VERSION 5.7 ;
  NOWIREEXTENSIONATPIN ON ;
  DIVIDERCHAR "/" ;
  BUSBITCHARS "[]" ;
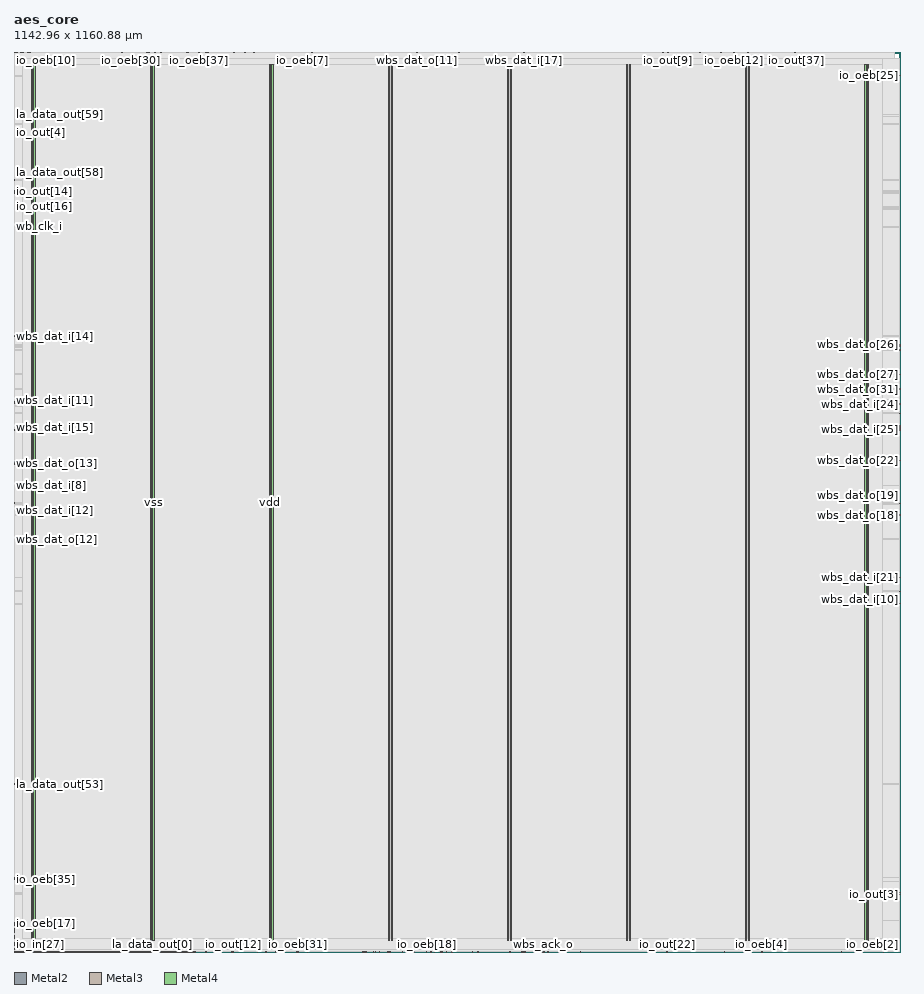
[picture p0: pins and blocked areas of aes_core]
MACRO aes_core
  CLASS BLOCK ;
  FOREIGN aes_core ;
  ORIGIN 0.000 0.000 ;
  SIZE 1142.960 BY 1160.880 ;
  PIN io_in[0]
    DIRECTION INPUT ;
    USE SIGNAL ;
    PORT
      LAYER Metal2 ;
        RECT 4.480 0.000 5.040 0.560 ;
    END
  END io_in[0]
  PIN io_in[10]
    DIRECTION INPUT ;
    USE SIGNAL ;
    PORT
      LAYER Metal2 ;
        RECT 12.320 0.000 12.880 0.560 ;
    END
  END io_in[10]
  PIN io_in[11]
    DIRECTION INPUT ;
    USE SIGNAL ;
    PORT
      LAYER Metal2 ;
        RECT 112.000 0.000 112.560 0.560 ;
    END
  END io_in[11]
  PIN io_in[12]
    DIRECTION INPUT ;
    USE SIGNAL ;
    PORT
      LAYER Metal2 ;
        RECT 13.440 0.000 14.000 0.560 ;
    END
  END io_in[12]
  PIN io_in[13]
    DIRECTION INPUT ;
    USE SIGNAL ;
    PORT
      LAYER Metal2 ;
        RECT 6.720 0.000 7.280 0.560 ;
    END
  END io_in[13]
  PIN io_in[14]
    DIRECTION INPUT ;
    USE SIGNAL ;
    PORT
      LAYER Metal2 ;
        RECT 10.080 0.000 10.640 0.560 ;
    END
  END io_in[14]
  PIN io_in[15]
    DIRECTION INPUT ;
    USE SIGNAL ;
    PORT
      LAYER Metal2 ;
        RECT 8.960 0.000 9.520 0.560 ;
    END
  END io_in[15]
  PIN io_in[16]
    DIRECTION INPUT ;
    USE SIGNAL ;
    PORT
      LAYER Metal2 ;
        RECT 16.800 0.000 17.360 0.560 ;
    END
  END io_in[16]
  PIN io_in[17]
    DIRECTION INPUT ;
    USE SIGNAL ;
    PORT
      LAYER Metal2 ;
        RECT 21.280 0.000 21.840 0.560 ;
    END
  END io_in[17]
  PIN io_in[18]
    DIRECTION INPUT ;
    USE SIGNAL ;
    PORT
      LAYER Metal2 ;
        RECT 14.560 0.000 15.120 0.560 ;
    END
  END io_in[18]
  PIN io_in[19]
    DIRECTION INPUT ;
    USE SIGNAL ;
    PORT
      LAYER Metal2 ;
        RECT 23.520 0.000 24.080 0.560 ;
    END
  END io_in[19]
  PIN io_in[1]
    DIRECTION INPUT ;
    USE SIGNAL ;
    PORT
      LAYER Metal2 ;
        RECT 22.400 0.000 22.960 0.560 ;
    END
  END io_in[1]
  PIN io_in[20]
    DIRECTION INPUT ;
    USE SIGNAL ;
    PORT
      LAYER Metal2 ;
        RECT 15.680 0.000 16.240 0.560 ;
    END
  END io_in[20]
  PIN io_in[21]
    DIRECTION INPUT ;
    USE SIGNAL ;
    PORT
      LAYER Metal2 ;
        RECT 19.040 0.000 19.600 0.560 ;
    END
  END io_in[21]
  PIN io_in[22]
    DIRECTION INPUT ;
    USE SIGNAL ;
    PORT
      LAYER Metal2 ;
        RECT 17.920 0.000 18.480 0.560 ;
    END
  END io_in[22]
  PIN io_in[23]
    DIRECTION INPUT ;
    USE SIGNAL ;
    PORT
      LAYER Metal2 ;
        RECT 25.760 0.000 26.320 0.560 ;
    END
  END io_in[23]
  PIN io_in[24]
    DIRECTION INPUT ;
    USE SIGNAL ;
    PORT
      LAYER Metal2 ;
        RECT 20.160 0.000 20.720 0.560 ;
    END
  END io_in[24]
  PIN io_in[25]
    DIRECTION INPUT ;
    USE SIGNAL ;
    PORT
      LAYER Metal2 ;
        RECT 31.360 0.000 31.920 0.560 ;
    END
  END io_in[25]
  PIN io_in[26]
    DIRECTION INPUT ;
    USE SIGNAL ;
    PORT
      LAYER Metal2 ;
        RECT 30.240 0.000 30.800 0.560 ;
    END
  END io_in[26]
  PIN io_in[27]
    DIRECTION INPUT ;
    USE SIGNAL ;
    PORT
      LAYER Metal2 ;
        RECT 33.600 0.000 34.160 0.560 ;
    END
  END io_in[27]
  PIN io_in[28]
    DIRECTION INPUT ;
    USE SIGNAL ;
    PORT
      LAYER Metal2 ;
        RECT 24.640 0.000 25.200 0.560 ;
    END
  END io_in[28]
  PIN io_in[29]
    DIRECTION INPUT ;
    USE SIGNAL ;
    PORT
      LAYER Metal2 ;
        RECT 28.000 0.000 28.560 0.560 ;
    END
  END io_in[29]
  PIN io_in[2]
    DIRECTION INPUT ;
    USE SIGNAL ;
    PORT
      LAYER Metal2 ;
        RECT 26.880 0.000 27.440 0.560 ;
    END
  END io_in[2]
  PIN io_in[30]
    DIRECTION INPUT ;
    USE SIGNAL ;
    PORT
      LAYER Metal2 ;
        RECT 34.720 0.000 35.280 0.560 ;
    END
  END io_in[30]
  PIN io_in[31]
    DIRECTION INPUT ;
    USE SIGNAL ;
    PORT
      LAYER Metal2 ;
        RECT 29.120 0.000 29.680 0.560 ;
    END
  END io_in[31]
  PIN io_in[32]
    DIRECTION INPUT ;
    USE SIGNAL ;
    PORT
      LAYER Metal2 ;
        RECT 32.480 0.000 33.040 0.560 ;
    END
  END io_in[32]
  PIN io_in[33]
    DIRECTION INPUT ;
    USE SIGNAL ;
    PORT
      LAYER Metal2 ;
        RECT 39.200 0.000 39.760 0.560 ;
    END
  END io_in[33]
  PIN io_in[34]
    DIRECTION INPUT ;
    USE SIGNAL ;
    PORT
      LAYER Metal2 ;
        RECT 40.320 0.000 40.880 0.560 ;
    END
  END io_in[34]
  PIN io_in[35]
    DIRECTION INPUT ;
    USE SIGNAL ;
    PORT
      LAYER Metal2 ;
        RECT 43.680 0.000 44.240 0.560 ;
    END
  END io_in[35]
  PIN io_in[36]
    DIRECTION INPUT ;
    USE SIGNAL ;
    PORT
      LAYER Metal2 ;
        RECT 36.960 0.000 37.520 0.560 ;
    END
  END io_in[36]
  PIN io_in[37]
    DIRECTION INPUT ;
    USE SIGNAL ;
    PORT
      LAYER Metal2 ;
        RECT 35.840 0.000 36.400 0.560 ;
    END
  END io_in[37]
  PIN io_in[3]
    DIRECTION INPUT ;
    USE SIGNAL ;
    PORT
      LAYER Metal2 ;
        RECT 47.040 0.000 47.600 0.560 ;
    END
  END io_in[3]
  PIN io_in[4]
    DIRECTION INPUT ;
    USE SIGNAL ;
    PORT
      LAYER Metal2 ;
        RECT 38.080 0.000 38.640 0.560 ;
    END
  END io_in[4]
  PIN io_in[5]
    DIRECTION INPUT ;
    USE SIGNAL ;
    PORT
      LAYER Metal2 ;
        RECT 41.440 0.000 42.000 0.560 ;
    END
  END io_in[5]
  PIN io_in[6]
    DIRECTION INPUT ;
    USE SIGNAL ;
    PORT
      LAYER Metal2 ;
        RECT 48.160 0.000 48.720 0.560 ;
    END
  END io_in[6]
  PIN io_in[7]
    DIRECTION INPUT ;
    USE SIGNAL ;
    PORT
      LAYER Metal2 ;
        RECT 49.280 0.000 49.840 0.560 ;
    END
  END io_in[7]
  PIN io_in[8]
    DIRECTION INPUT ;
    USE SIGNAL ;
    PORT
      LAYER Metal2 ;
        RECT 42.560 0.000 43.120 0.560 ;
    END
  END io_in[8]
  PIN io_in[9]
    DIRECTION INPUT ;
    USE SIGNAL ;
    PORT
      LAYER Metal2 ;
        RECT 45.920 0.000 46.480 0.560 ;
    END
  END io_in[9]
  PIN io_oeb[0]
    DIRECTION OUTPUT ;
    USE SIGNAL ;
    ANTENNADIFFAREA 0.360800 ;
    PORT
      LAYER Metal2 ;
        RECT 265.440 0.000 266.000 0.560 ;
    END
  END io_oeb[0]
  PIN io_oeb[10]
    DIRECTION OUTPUT ;
    USE SIGNAL ;
    ANTENNADIFFAREA 0.360800 ;
    PORT
      LAYER Metal2 ;
        RECT 15.680 1160.320 16.240 1160.880 ;
    END
  END io_oeb[10]
  PIN io_oeb[11]
    DIRECTION OUTPUT ;
    USE SIGNAL ;
    ANTENNADIFFAREA 0.360800 ;
    PORT
      LAYER Metal3 ;
        RECT 0.000 3.360 0.560 3.920 ;
    END
  END io_oeb[11]
  PIN io_oeb[12]
    DIRECTION OUTPUT ;
    USE SIGNAL ;
    ANTENNADIFFAREA 0.360800 ;
    PORT
      LAYER Metal2 ;
        RECT 928.480 1160.320 929.040 1160.880 ;
    END
  END io_oeb[12]
  PIN io_oeb[13]
    DIRECTION OUTPUT ;
    USE SIGNAL ;
    ANTENNADIFFAREA 0.360800 ;
    PORT
      LAYER Metal3 ;
        RECT 0.000 10.080 0.560 10.640 ;
    END
  END io_oeb[13]
  PIN io_oeb[14]
    DIRECTION OUTPUT ;
    USE SIGNAL ;
    ANTENNADIFFAREA 0.360800 ;
    PORT
      LAYER Metal2 ;
        RECT 916.160 0.000 916.720 0.560 ;
    END
  END io_oeb[14]
  PIN io_oeb[15]
    DIRECTION OUTPUT ;
    USE SIGNAL ;
    ANTENNADIFFAREA 0.360800 ;
    PORT
      LAYER Metal3 ;
        RECT 0.000 31.360 0.560 31.920 ;
    END
  END io_oeb[15]
  PIN io_oeb[16]
    DIRECTION OUTPUT ;
    USE SIGNAL ;
    ANTENNADIFFAREA 0.360800 ;
    PORT
      LAYER Metal2 ;
        RECT 2.240 1160.320 2.800 1160.880 ;
    END
  END io_oeb[16]
  PIN io_oeb[17]
    DIRECTION OUTPUT ;
    USE SIGNAL ;
    ANTENNADIFFAREA 0.360800 ;
    PORT
      LAYER Metal3 ;
        RECT 0.000 35.840 0.560 36.400 ;
    END
  END io_oeb[17]
  PIN io_oeb[18]
    DIRECTION OUTPUT ;
    USE SIGNAL ;
    ANTENNADIFFAREA 0.360800 ;
    PORT
      LAYER Metal2 ;
        RECT 532.000 0.000 532.560 0.560 ;
    END
  END io_oeb[18]
  PIN io_oeb[19]
    DIRECTION OUTPUT ;
    USE SIGNAL ;
    ANTENNADIFFAREA 0.360800 ;
    PORT
      LAYER Metal2 ;
        RECT 7.840 1160.320 8.400 1160.880 ;
    END
  END io_oeb[19]
  PIN io_oeb[1]
    DIRECTION OUTPUT ;
    USE SIGNAL ;
    ANTENNADIFFAREA 0.360800 ;
    PORT
      LAYER Metal2 ;
        RECT 182.560 1160.320 183.120 1160.880 ;
    END
  END io_oeb[1]
  PIN io_oeb[20]
    DIRECTION OUTPUT ;
    USE SIGNAL ;
    ANTENNADIFFAREA 0.360800 ;
    PORT
      LAYER Metal2 ;
        RECT 172.480 1160.320 173.040 1160.880 ;
    END
  END io_oeb[20]
  PIN io_oeb[21]
    DIRECTION OUTPUT ;
    USE SIGNAL ;
    ANTENNADIFFAREA 0.360800 ;
    PORT
      LAYER Metal3 ;
        RECT 0.000 29.120 0.560 29.680 ;
    END
  END io_oeb[21]
  PIN io_oeb[22]
    DIRECTION OUTPUT ;
    USE SIGNAL ;
    ANTENNADIFFAREA 0.360800 ;
    PORT
      LAYER Metal2 ;
        RECT 16.800 1160.320 17.360 1160.880 ;
    END
  END io_oeb[22]
  PIN io_oeb[23]
    DIRECTION OUTPUT ;
    USE SIGNAL ;
    ANTENNADIFFAREA 0.360800 ;
    PORT
      LAYER Metal2 ;
        RECT 1.120 1160.320 1.680 1160.880 ;
    END
  END io_oeb[23]
  PIN io_oeb[24]
    DIRECTION OUTPUT ;
    USE SIGNAL ;
    ANTENNADIFFAREA 0.360800 ;
    PORT
      LAYER Metal3 ;
        RECT 0.000 19.040 0.560 19.600 ;
    END
  END io_oeb[24]
  PIN io_oeb[25]
    DIRECTION OUTPUT ;
    USE SIGNAL ;
    ANTENNADIFFAREA 0.360800 ;
    PORT
      LAYER Metal3 ;
        RECT 1142.400 1130.080 1142.960 1130.640 ;
    END
  END io_oeb[25]
  PIN io_oeb[26]
    DIRECTION OUTPUT ;
    USE SIGNAL ;
    ANTENNADIFFAREA 0.360800 ;
    PORT
      LAYER Metal3 ;
        RECT 0.000 32.480 0.560 33.040 ;
    END
  END io_oeb[26]
  PIN io_oeb[27]
    DIRECTION OUTPUT ;
    USE SIGNAL ;
    ANTENNADIFFAREA 0.360800 ;
    PORT
      LAYER Metal3 ;
        RECT 0.000 8.960 0.560 9.520 ;
    END
  END io_oeb[27]
  PIN io_oeb[28]
    DIRECTION OUTPUT ;
    USE SIGNAL ;
    ANTENNADIFFAREA 0.360800 ;
    PORT
      LAYER Metal3 ;
        RECT 0.000 17.920 0.560 18.480 ;
    END
  END io_oeb[28]
  PIN io_oeb[29]
    DIRECTION OUTPUT ;
    USE SIGNAL ;
    ANTENNADIFFAREA 0.360800 ;
    PORT
      LAYER Metal2 ;
        RECT 549.920 0.000 550.480 0.560 ;
    END
  END io_oeb[29]
  PIN io_oeb[2]
    DIRECTION OUTPUT ;
    USE SIGNAL ;
    ANTENNADIFFAREA 0.360800 ;
    PORT
      LAYER Metal2 ;
        RECT 1121.120 0.000 1121.680 0.560 ;
    END
  END io_oeb[2]
  PIN io_oeb[30]
    DIRECTION OUTPUT ;
    USE SIGNAL ;
    ANTENNADIFFAREA 0.360800 ;
    PORT
      LAYER Metal2 ;
        RECT 150.080 1160.320 150.640 1160.880 ;
    END
  END io_oeb[30]
  PIN io_oeb[31]
    DIRECTION OUTPUT ;
    USE SIGNAL ;
    ANTENNADIFFAREA 0.360800 ;
    PORT
      LAYER Metal2 ;
        RECT 366.240 0.000 366.800 0.560 ;
    END
  END io_oeb[31]
  PIN io_oeb[32]
    DIRECTION OUTPUT ;
    USE SIGNAL ;
    ANTENNADIFFAREA 0.360800 ;
    PORT
      LAYER Metal2 ;
        RECT 21.280 1160.320 21.840 1160.880 ;
    END
  END io_oeb[32]
  PIN io_oeb[33]
    DIRECTION OUTPUT ;
    USE SIGNAL ;
    ANTENNADIFFAREA 0.360800 ;
    PORT
      LAYER Metal2 ;
        RECT 171.360 1160.320 171.920 1160.880 ;
    END
  END io_oeb[33]
  PIN io_oeb[34]
    DIRECTION OUTPUT ;
    USE SIGNAL ;
    ANTENNADIFFAREA 0.360800 ;
    PORT
      LAYER Metal2 ;
        RECT 173.600 1160.320 174.160 1160.880 ;
    END
  END io_oeb[34]
  PIN io_oeb[35]
    DIRECTION OUTPUT ;
    USE SIGNAL ;
    ANTENNADIFFAREA 0.360800 ;
    PORT
      LAYER Metal3 ;
        RECT 0.000 92.960 0.560 93.520 ;
    END
  END io_oeb[35]
  PIN io_oeb[36]
    DIRECTION OUTPUT ;
    USE SIGNAL ;
    ANTENNADIFFAREA 0.360800 ;
    PORT
      LAYER Metal2 ;
        RECT 946.400 1160.320 946.960 1160.880 ;
    END
  END io_oeb[36]
  PIN io_oeb[37]
    DIRECTION OUTPUT ;
    USE SIGNAL ;
    ANTENNADIFFAREA 0.360800 ;
    PORT
      LAYER Metal2 ;
        RECT 238.560 1160.320 239.120 1160.880 ;
    END
  END io_oeb[37]
  PIN io_oeb[3]
    DIRECTION OUTPUT ;
    USE SIGNAL ;
    ANTENNADIFFAREA 0.360800 ;
    PORT
      LAYER Metal2 ;
        RECT 14.560 1160.320 15.120 1160.880 ;
    END
  END io_oeb[3]
  PIN io_oeb[4]
    DIRECTION OUTPUT ;
    USE SIGNAL ;
    ANTENNADIFFAREA 0.360800 ;
    PORT
      LAYER Metal2 ;
        RECT 964.320 0.000 964.880 0.560 ;
    END
  END io_oeb[4]
  PIN io_oeb[5]
    DIRECTION OUTPUT ;
    USE SIGNAL ;
    ANTENNADIFFAREA 0.360800 ;
    PORT
      LAYER Metal3 ;
        RECT 0.000 20.160 0.560 20.720 ;
    END
  END io_oeb[5]
  PIN io_oeb[6]
    DIRECTION OUTPUT ;
    USE SIGNAL ;
    ANTENNADIFFAREA 0.360800 ;
    PORT
      LAYER Metal2 ;
        RECT 247.520 0.000 248.080 0.560 ;
    END
  END io_oeb[6]
  PIN io_oeb[7]
    DIRECTION OUTPUT ;
    USE SIGNAL ;
    ANTENNADIFFAREA 0.360800 ;
    PORT
      LAYER Metal2 ;
        RECT 371.840 1160.320 372.400 1160.880 ;
    END
  END io_oeb[7]
  PIN io_oeb[8]
    DIRECTION OUTPUT ;
    USE SIGNAL ;
    ANTENNADIFFAREA 0.360800 ;
    PORT
      LAYER Metal2 ;
        RECT 11.200 1160.320 11.760 1160.880 ;
    END
  END io_oeb[8]
  PIN io_oeb[9]
    DIRECTION OUTPUT ;
    USE SIGNAL ;
    ANTENNADIFFAREA 0.360800 ;
    PORT
      LAYER Metal3 ;
        RECT 0.000 28.000 0.560 28.560 ;
    END
  END io_oeb[9]
  PIN io_out[0]
    DIRECTION OUTPUT ;
    USE SIGNAL ;
    ANTENNADIFFAREA 0.360800 ;
    PORT
      LAYER Metal2 ;
        RECT 176.960 1160.320 177.520 1160.880 ;
    END
  END io_out[0]
  PIN io_out[10]
    DIRECTION OUTPUT ;
    USE SIGNAL ;
    ANTENNADIFFAREA 0.360800 ;
    PORT
      LAYER Metal2 ;
        RECT 178.080 1160.320 178.640 1160.880 ;
    END
  END io_out[10]
  PIN io_out[11]
    DIRECTION OUTPUT ;
    USE SIGNAL ;
    ANTENNADIFFAREA 0.360800 ;
    PORT
      LAYER Metal2 ;
        RECT 123.200 0.000 123.760 0.560 ;
    END
  END io_out[11]
  PIN io_out[12]
    DIRECTION OUTPUT ;
    USE SIGNAL ;
    ANTENNADIFFAREA 0.360800 ;
    PORT
      LAYER Metal2 ;
        RECT 282.240 0.000 282.800 0.560 ;
    END
  END io_out[12]
  PIN io_out[13]
    DIRECTION OUTPUT ;
    USE SIGNAL ;
    ANTENNADIFFAREA 0.360800 ;
    PORT
      LAYER Metal2 ;
        RECT 10.080 1160.320 10.640 1160.880 ;
    END
  END io_out[13]
  PIN io_out[14]
    DIRECTION OUTPUT ;
    USE SIGNAL ;
    ANTENNADIFFAREA 0.360800 ;
    PORT
      LAYER Metal3 ;
        RECT 0.000 981.120 0.560 981.680 ;
    END
  END io_out[14]
  PIN io_out[15]
    DIRECTION OUTPUT ;
    USE SIGNAL ;
    ANTENNADIFFAREA 0.360800 ;
    PORT
      LAYER Metal3 ;
        RECT 0.000 95.200 0.560 95.760 ;
    END
  END io_out[15]
  PIN io_out[16]
    DIRECTION OUTPUT ;
    USE SIGNAL ;
    ANTENNADIFFAREA 0.360800 ;
    PORT
      LAYER Metal3 ;
        RECT 0.000 960.960 0.560 961.520 ;
    END
  END io_out[16]
  PIN io_out[17]
    DIRECTION OUTPUT ;
    USE SIGNAL ;
    ANTENNADIFFAREA 0.360800 ;
    PORT
      LAYER Metal2 ;
        RECT 364.000 0.000 364.560 0.560 ;
    END
  END io_out[17]
  PIN io_out[18]
    DIRECTION OUTPUT ;
    USE SIGNAL ;
    ANTENNADIFFAREA 0.360800 ;
    PORT
      LAYER Metal3 ;
        RECT 0.000 7.840 0.560 8.400 ;
    END
  END io_out[18]
  PIN io_out[19]
    DIRECTION OUTPUT ;
    USE SIGNAL ;
    ANTENNADIFFAREA 0.360800 ;
    PORT
      LAYER Metal2 ;
        RECT 20.160 1160.320 20.720 1160.880 ;
    END
  END io_out[19]
  PIN io_out[1]
    DIRECTION OUTPUT ;
    USE SIGNAL ;
    ANTENNADIFFAREA 0.360800 ;
    PORT
      LAYER Metal3 ;
        RECT 0.000 38.080 0.560 38.640 ;
    END
  END io_out[1]
  PIN io_out[20]
    DIRECTION OUTPUT ;
    USE SIGNAL ;
    ANTENNADIFFAREA 0.360800 ;
    PORT
      LAYER Metal2 ;
        RECT 284.480 1160.320 285.040 1160.880 ;
    END
  END io_out[20]
  PIN io_out[21]
    DIRECTION OUTPUT ;
    USE SIGNAL ;
    ANTENNADIFFAREA 0.360800 ;
    PORT
      LAYER Metal2 ;
        RECT 884.800 1160.320 885.360 1160.880 ;
    END
  END io_out[21]
  PIN io_out[22]
    DIRECTION OUTPUT ;
    USE SIGNAL ;
    ANTENNADIFFAREA 0.360800 ;
    PORT
      LAYER Metal2 ;
        RECT 842.240 0.000 842.800 0.560 ;
    END
  END io_out[22]
  PIN io_out[23]
    DIRECTION OUTPUT ;
    USE SIGNAL ;
    ANTENNADIFFAREA 0.360800 ;
    PORT
      LAYER Metal2 ;
        RECT 3.360 1160.320 3.920 1160.880 ;
    END
  END io_out[23]
  PIN io_out[24]
    DIRECTION OUTPUT ;
    USE SIGNAL ;
    ANTENNADIFFAREA 0.360800 ;
    PORT
      LAYER Metal3 ;
        RECT 0.000 978.880 0.560 979.440 ;
    END
  END io_out[24]
  PIN io_out[25]
    DIRECTION OUTPUT ;
    USE SIGNAL ;
    ANTENNADIFFAREA 0.360800 ;
    PORT
      LAYER Metal2 ;
        RECT 104.160 0.000 104.720 0.560 ;
    END
  END io_out[25]
  PIN io_out[26]
    DIRECTION OUTPUT ;
    USE SIGNAL ;
    ANTENNADIFFAREA 0.360800 ;
    PORT
      LAYER Metal2 ;
        RECT 138.880 0.000 139.440 0.560 ;
    END
  END io_out[26]
  PIN io_out[27]
    DIRECTION OUTPUT ;
    USE SIGNAL ;
    ANTENNADIFFAREA 0.360800 ;
    PORT
      LAYER Metal2 ;
        RECT 324.800 0.000 325.360 0.560 ;
    END
  END io_out[27]
  PIN io_out[28]
    DIRECTION OUTPUT ;
    USE SIGNAL ;
    ANTENNADIFFAREA 0.360800 ;
    PORT
      LAYER Metal2 ;
        RECT 175.840 1160.320 176.400 1160.880 ;
    END
  END io_out[28]
  PIN io_out[29]
    DIRECTION OUTPUT ;
    USE SIGNAL ;
    ANTENNADIFFAREA 0.360800 ;
    PORT
      LAYER Metal2 ;
        RECT 841.120 0.000 841.680 0.560 ;
    END
  END io_out[29]
  PIN io_out[2]
    DIRECTION OUTPUT ;
    USE SIGNAL ;
    ANTENNADIFFAREA 0.360800 ;
    PORT
      LAYER Metal2 ;
        RECT 17.920 1160.320 18.480 1160.880 ;
    END
  END io_out[2]
  PIN io_out[30]
    DIRECTION OUTPUT ;
    USE SIGNAL ;
    ANTENNADIFFAREA 0.360800 ;
    PORT
      LAYER Metal2 ;
        RECT 13.440 1160.320 14.000 1160.880 ;
    END
  END io_out[30]
  PIN io_out[31]
    DIRECTION OUTPUT ;
    USE SIGNAL ;
    ANTENNADIFFAREA 0.360800 ;
    PORT
      LAYER Metal2 ;
        RECT 216.160 0.000 216.720 0.560 ;
    END
  END io_out[31]
  PIN io_out[32]
    DIRECTION OUTPUT ;
    USE SIGNAL ;
    ANTENNADIFFAREA 0.360800 ;
    PORT
      LAYER Metal2 ;
        RECT 313.600 0.000 314.160 0.560 ;
    END
  END io_out[32]
  PIN io_out[33]
    DIRECTION OUTPUT ;
    USE SIGNAL ;
    ANTENNADIFFAREA 0.360800 ;
    PORT
      LAYER Metal2 ;
        RECT 247.520 1160.320 248.080 1160.880 ;
    END
  END io_out[33]
  PIN io_out[34]
    DIRECTION OUTPUT ;
    USE SIGNAL ;
    ANTENNADIFFAREA 0.360800 ;
    PORT
      LAYER Metal2 ;
        RECT 384.160 1160.320 384.720 1160.880 ;
    END
  END io_out[34]
  PIN io_out[35]
    DIRECTION OUTPUT ;
    USE SIGNAL ;
    ANTENNADIFFAREA 0.360800 ;
    PORT
      LAYER Metal2 ;
        RECT 280.000 0.000 280.560 0.560 ;
    END
  END io_out[35]
  PIN io_out[36]
    DIRECTION OUTPUT ;
    USE SIGNAL ;
    ANTENNADIFFAREA 0.360800 ;
    PORT
      LAYER Metal2 ;
        RECT 1067.360 0.000 1067.920 0.560 ;
    END
  END io_out[36]
  PIN io_out[37]
    DIRECTION OUTPUT ;
    USE SIGNAL ;
    ANTENNADIFFAREA 0.360800 ;
    PORT
      LAYER Metal2 ;
        RECT 1009.120 1160.320 1009.680 1160.880 ;
    END
  END io_out[37]
  PIN io_out[3]
    DIRECTION OUTPUT ;
    USE SIGNAL ;
    ANTENNADIFFAREA 0.360800 ;
    PORT
      LAYER Metal3 ;
        RECT 1142.400 73.920 1142.960 74.480 ;
    END
  END io_out[3]
  PIN io_out[4]
    DIRECTION OUTPUT ;
    USE SIGNAL ;
    ANTENNADIFFAREA 0.360800 ;
    PORT
      LAYER Metal3 ;
        RECT 0.000 1067.360 0.560 1067.920 ;
    END
  END io_out[4]
  PIN io_out[5]
    DIRECTION OUTPUT ;
    USE SIGNAL ;
    ANTENNADIFFAREA 0.360800 ;
    PORT
      LAYER Metal3 ;
        RECT 0.000 22.400 0.560 22.960 ;
    END
  END io_out[5]
  PIN io_out[6]
    DIRECTION OUTPUT ;
    USE SIGNAL ;
    ANTENNADIFFAREA 0.360800 ;
    PORT
      LAYER Metal3 ;
        RECT 0.000 24.640 0.560 25.200 ;
    END
  END io_out[6]
  PIN io_out[7]
    DIRECTION OUTPUT ;
    USE SIGNAL ;
    ANTENNADIFFAREA 0.360800 ;
    PORT
      LAYER Metal2 ;
        RECT 236.320 1160.320 236.880 1160.880 ;
    END
  END io_out[7]
  PIN io_out[8]
    DIRECTION OUTPUT ;
    USE SIGNAL ;
    ANTENNADIFFAREA 0.360800 ;
    PORT
      LAYER Metal2 ;
        RECT 91.840 0.000 92.400 0.560 ;
    END
  END io_out[8]
  PIN io_out[9]
    DIRECTION OUTPUT ;
    USE SIGNAL ;
    ANTENNADIFFAREA 0.360800 ;
    PORT
      LAYER Metal2 ;
        RECT 843.360 1160.320 843.920 1160.880 ;
    END
  END io_out[9]
  PIN la_data_in[0]
    DIRECTION INPUT ;
    USE SIGNAL ;
    PORT
      LAYER Metal2 ;
        RECT 44.800 0.000 45.360 0.560 ;
    END
  END la_data_in[0]
  PIN la_data_in[10]
    DIRECTION INPUT ;
    USE SIGNAL ;
    PORT
      LAYER Metal2 ;
        RECT 52.640 0.000 53.200 0.560 ;
    END
  END la_data_in[10]
  PIN la_data_in[11]
    DIRECTION INPUT ;
    USE SIGNAL ;
    PORT
      LAYER Metal2 ;
        RECT 57.120 0.000 57.680 0.560 ;
    END
  END la_data_in[11]
  PIN la_data_in[12]
    DIRECTION INPUT ;
    USE SIGNAL ;
    PORT
      LAYER Metal2 ;
        RECT 50.400 0.000 50.960 0.560 ;
    END
  END la_data_in[12]
  PIN la_data_in[13]
    DIRECTION INPUT ;
    USE SIGNAL ;
    PORT
      LAYER Metal2 ;
        RECT 59.360 0.000 59.920 0.560 ;
    END
  END la_data_in[13]
  PIN la_data_in[14]
    DIRECTION INPUT ;
    USE SIGNAL ;
    PORT
      LAYER Metal2 ;
        RECT 58.240 0.000 58.800 0.560 ;
    END
  END la_data_in[14]
  PIN la_data_in[15]
    DIRECTION INPUT ;
    USE SIGNAL ;
    PORT
      LAYER Metal2 ;
        RECT 51.520 0.000 52.080 0.560 ;
    END
  END la_data_in[15]
  PIN la_data_in[16]
    DIRECTION INPUT ;
    USE SIGNAL ;
    PORT
      LAYER Metal2 ;
        RECT 54.880 0.000 55.440 0.560 ;
    END
  END la_data_in[16]
  PIN la_data_in[17]
    DIRECTION INPUT ;
    USE SIGNAL ;
    PORT
      LAYER Metal2 ;
        RECT 53.760 0.000 54.320 0.560 ;
    END
  END la_data_in[17]
  PIN la_data_in[18]
    DIRECTION INPUT ;
    USE SIGNAL ;
    PORT
      LAYER Metal2 ;
        RECT 61.600 0.000 62.160 0.560 ;
    END
  END la_data_in[18]
  PIN la_data_in[19]
    DIRECTION INPUT ;
    USE SIGNAL ;
    PORT
      LAYER Metal2 ;
        RECT 56.000 0.000 56.560 0.560 ;
    END
  END la_data_in[19]
  PIN la_data_in[1]
    DIRECTION INPUT ;
    USE SIGNAL ;
    PORT
      LAYER Metal2 ;
        RECT 67.200 0.000 67.760 0.560 ;
    END
  END la_data_in[1]
  PIN la_data_in[20]
    DIRECTION INPUT ;
    USE SIGNAL ;
    PORT
      LAYER Metal2 ;
        RECT 66.080 0.000 66.640 0.560 ;
    END
  END la_data_in[20]
  PIN la_data_in[21]
    DIRECTION INPUT ;
    USE SIGNAL ;
    PORT
      LAYER Metal2 ;
        RECT 69.440 0.000 70.000 0.560 ;
    END
  END la_data_in[21]
  PIN la_data_in[22]
    DIRECTION INPUT ;
    USE SIGNAL ;
    PORT
      LAYER Metal2 ;
        RECT 60.480 0.000 61.040 0.560 ;
    END
  END la_data_in[22]
  PIN la_data_in[23]
    DIRECTION INPUT ;
    USE SIGNAL ;
    PORT
      LAYER Metal2 ;
        RECT 63.840 0.000 64.400 0.560 ;
    END
  END la_data_in[23]
  PIN la_data_in[24]
    DIRECTION INPUT ;
    USE SIGNAL ;
    PORT
      LAYER Metal2 ;
        RECT 62.720 0.000 63.280 0.560 ;
    END
  END la_data_in[24]
  PIN la_data_in[25]
    DIRECTION INPUT ;
    USE SIGNAL ;
    PORT
      LAYER Metal2 ;
        RECT 70.560 0.000 71.120 0.560 ;
    END
  END la_data_in[25]
  PIN la_data_in[26]
    DIRECTION INPUT ;
    USE SIGNAL ;
    PORT
      LAYER Metal2 ;
        RECT 64.960 0.000 65.520 0.560 ;
    END
  END la_data_in[26]
  PIN la_data_in[27]
    DIRECTION INPUT ;
    USE SIGNAL ;
    PORT
      LAYER Metal2 ;
        RECT 68.320 0.000 68.880 0.560 ;
    END
  END la_data_in[27]
  PIN la_data_in[28]
    DIRECTION INPUT ;
    USE SIGNAL ;
    PORT
      LAYER Metal2 ;
        RECT 75.040 0.000 75.600 0.560 ;
    END
  END la_data_in[28]
  PIN la_data_in[29]
    DIRECTION INPUT ;
    USE SIGNAL ;
    PORT
      LAYER Metal2 ;
        RECT 76.160 0.000 76.720 0.560 ;
    END
  END la_data_in[29]
  PIN la_data_in[2]
    DIRECTION INPUT ;
    USE SIGNAL ;
    PORT
      LAYER Metal2 ;
        RECT 79.520 0.000 80.080 0.560 ;
    END
  END la_data_in[2]
  PIN la_data_in[30]
    DIRECTION INPUT ;
    USE SIGNAL ;
    PORT
      LAYER Metal2 ;
        RECT 72.800 0.000 73.360 0.560 ;
    END
  END la_data_in[30]
  PIN la_data_in[31]
    DIRECTION INPUT ;
    USE SIGNAL ;
    PORT
      LAYER Metal2 ;
        RECT 71.680 0.000 72.240 0.560 ;
    END
  END la_data_in[31]
  PIN la_data_in[32]
    DIRECTION INPUT ;
    USE SIGNAL ;
    PORT
      LAYER Metal2 ;
        RECT 82.880 0.000 83.440 0.560 ;
    END
  END la_data_in[32]
  PIN la_data_in[33]
    DIRECTION INPUT ;
    USE SIGNAL ;
    PORT
      LAYER Metal2 ;
        RECT 73.920 0.000 74.480 0.560 ;
    END
  END la_data_in[33]
  PIN la_data_in[34]
    DIRECTION INPUT ;
    USE SIGNAL ;
    PORT
      LAYER Metal2 ;
        RECT 77.280 0.000 77.840 0.560 ;
    END
  END la_data_in[34]
  PIN la_data_in[35]
    DIRECTION INPUT ;
    USE SIGNAL ;
    PORT
      LAYER Metal2 ;
        RECT 84.000 0.000 84.560 0.560 ;
    END
  END la_data_in[35]
  PIN la_data_in[36]
    DIRECTION INPUT ;
    USE SIGNAL ;
    PORT
      LAYER Metal2 ;
        RECT 85.120 0.000 85.680 0.560 ;
    END
  END la_data_in[36]
  PIN la_data_in[37]
    DIRECTION INPUT ;
    USE SIGNAL ;
    PORT
      LAYER Metal2 ;
        RECT 78.400 0.000 78.960 0.560 ;
    END
  END la_data_in[37]
  PIN la_data_in[38]
    DIRECTION INPUT ;
    USE SIGNAL ;
    PORT
      LAYER Metal2 ;
        RECT 81.760 0.000 82.320 0.560 ;
    END
  END la_data_in[38]
  PIN la_data_in[39]
    DIRECTION INPUT ;
    USE SIGNAL ;
    PORT
      LAYER Metal2 ;
        RECT 80.640 0.000 81.200 0.560 ;
    END
  END la_data_in[39]
  PIN la_data_in[3]
    DIRECTION INPUT ;
    USE SIGNAL ;
    PORT
      LAYER Metal2 ;
        RECT 88.480 0.000 89.040 0.560 ;
    END
  END la_data_in[3]
  PIN la_data_in[40]
    DIRECTION INPUT ;
    USE SIGNAL ;
    PORT
      LAYER Metal2 ;
        RECT 224.000 0.000 224.560 0.560 ;
    END
  END la_data_in[40]
  PIN la_data_in[41]
    DIRECTION INPUT ;
    USE SIGNAL ;
    PORT
      LAYER Metal2 ;
        RECT 86.240 0.000 86.800 0.560 ;
    END
  END la_data_in[41]
  PIN la_data_in[42]
    DIRECTION INPUT ;
    USE SIGNAL ;
    PORT
      LAYER Metal2 ;
        RECT 92.960 0.000 93.520 0.560 ;
    END
  END la_data_in[42]
  PIN la_data_in[43]
    DIRECTION INPUT ;
    USE SIGNAL ;
    PORT
      LAYER Metal2 ;
        RECT 94.080 0.000 94.640 0.560 ;
    END
  END la_data_in[43]
  PIN la_data_in[44]
    DIRECTION INPUT ;
    USE SIGNAL ;
    PORT
      LAYER Metal2 ;
        RECT 87.360 0.000 87.920 0.560 ;
    END
  END la_data_in[44]
  PIN la_data_in[45]
    DIRECTION INPUT ;
    USE SIGNAL ;
    PORT
      LAYER Metal2 ;
        RECT 218.400 0.000 218.960 0.560 ;
    END
  END la_data_in[45]
  PIN la_data_in[46]
    DIRECTION INPUT ;
    USE SIGNAL ;
    PORT
      LAYER Metal2 ;
        RECT 90.720 0.000 91.280 0.560 ;
    END
  END la_data_in[46]
  PIN la_data_in[47]
    DIRECTION INPUT ;
    USE SIGNAL ;
    PORT
      LAYER Metal2 ;
        RECT 97.440 0.000 98.000 0.560 ;
    END
  END la_data_in[47]
  PIN la_data_in[48]
    DIRECTION INPUT ;
    USE SIGNAL ;
    PORT
      LAYER Metal2 ;
        RECT 96.320 0.000 96.880 0.560 ;
    END
  END la_data_in[48]
  PIN la_data_in[49]
    DIRECTION INPUT ;
    USE SIGNAL ;
    PORT
      LAYER Metal2 ;
        RECT 5.600 0.000 6.160 0.560 ;
    END
  END la_data_in[49]
  PIN la_data_in[4]
    DIRECTION INPUT ;
    USE SIGNAL ;
    PORT
      LAYER Metal2 ;
        RECT 95.200 0.000 95.760 0.560 ;
    END
  END la_data_in[4]
  PIN la_data_in[50]
    DIRECTION INPUT ;
    USE SIGNAL ;
    PORT
      LAYER Metal2 ;
        RECT 100.800 0.000 101.360 0.560 ;
    END
  END la_data_in[50]
  PIN la_data_in[51]
    DIRECTION INPUT ;
    USE SIGNAL ;
    PORT
      LAYER Metal2 ;
        RECT 103.040 0.000 103.600 0.560 ;
    END
  END la_data_in[51]
  PIN la_data_in[52]
    DIRECTION INPUT ;
    USE SIGNAL ;
    PORT
      LAYER Metal2 ;
        RECT 101.920 0.000 102.480 0.560 ;
    END
  END la_data_in[52]
  PIN la_data_in[53]
    DIRECTION INPUT ;
    USE SIGNAL ;
    PORT
      LAYER Metal2 ;
        RECT 99.680 0.000 100.240 0.560 ;
    END
  END la_data_in[53]
  PIN la_data_in[54]
    DIRECTION INPUT ;
    USE SIGNAL ;
    PORT
      LAYER Metal2 ;
        RECT 98.560 0.000 99.120 0.560 ;
    END
  END la_data_in[54]
  PIN la_data_in[55]
    DIRECTION INPUT ;
    USE SIGNAL ;
    PORT
      LAYER Metal2 ;
        RECT 105.280 0.000 105.840 0.560 ;
    END
  END la_data_in[55]
  PIN la_data_in[56]
    DIRECTION INPUT ;
    USE SIGNAL ;
    PORT
      LAYER Metal2 ;
        RECT 106.400 0.000 106.960 0.560 ;
    END
  END la_data_in[56]
  PIN la_data_in[57]
    DIRECTION INPUT ;
    USE SIGNAL ;
    PORT
      LAYER Metal2 ;
        RECT 7.840 0.000 8.400 0.560 ;
    END
  END la_data_in[57]
  PIN la_data_in[58]
    DIRECTION INPUT ;
    USE SIGNAL ;
    PORT
      LAYER Metal2 ;
        RECT 110.880 0.000 111.440 0.560 ;
    END
  END la_data_in[58]
  PIN la_data_in[59]
    DIRECTION INPUT ;
    USE SIGNAL ;
    PORT
      LAYER Metal2 ;
        RECT 108.640 0.000 109.200 0.560 ;
    END
  END la_data_in[59]
  PIN la_data_in[5]
    DIRECTION INPUT ;
    USE SIGNAL ;
    PORT
      LAYER Metal2 ;
        RECT 221.760 0.000 222.320 0.560 ;
    END
  END la_data_in[5]
  PIN la_data_in[60]
    DIRECTION INPUT ;
    USE SIGNAL ;
    PORT
      LAYER Metal2 ;
        RECT 222.880 0.000 223.440 0.560 ;
    END
  END la_data_in[60]
  PIN la_data_in[61]
    DIRECTION INPUT ;
    USE SIGNAL ;
    PORT
      LAYER Metal2 ;
        RECT 107.520 0.000 108.080 0.560 ;
    END
  END la_data_in[61]
  PIN la_data_in[62]
    DIRECTION INPUT ;
    USE SIGNAL ;
    PORT
      LAYER Metal2 ;
        RECT 116.480 0.000 117.040 0.560 ;
    END
  END la_data_in[62]
  PIN la_data_in[63]
    DIRECTION INPUT ;
    USE SIGNAL ;
    PORT
      LAYER Metal2 ;
        RECT 109.760 0.000 110.320 0.560 ;
    END
  END la_data_in[63]
  PIN la_data_in[6]
    DIRECTION INPUT ;
    USE SIGNAL ;
    PORT
      LAYER Metal2 ;
        RECT 113.120 0.000 113.680 0.560 ;
    END
  END la_data_in[6]
  PIN la_data_in[7]
    DIRECTION INPUT ;
    USE SIGNAL ;
    PORT
      LAYER Metal2 ;
        RECT 220.640 0.000 221.200 0.560 ;
    END
  END la_data_in[7]
  PIN la_data_in[8]
    DIRECTION INPUT ;
    USE SIGNAL ;
    PORT
      LAYER Metal2 ;
        RECT 115.360 0.000 115.920 0.560 ;
    END
  END la_data_in[8]
  PIN la_data_in[9]
    DIRECTION INPUT ;
    USE SIGNAL ;
    PORT
      LAYER Metal2 ;
        RECT 114.240 0.000 114.800 0.560 ;
    END
  END la_data_in[9]
  PIN la_data_out[0]
    DIRECTION OUTPUT ;
    USE SIGNAL ;
    ANTENNADIFFAREA 0.360800 ;
    PORT
      LAYER Metal2 ;
        RECT 178.080 0.000 178.640 0.560 ;
    END
  END la_data_out[0]
  PIN la_data_out[10]
    DIRECTION OUTPUT ;
    USE SIGNAL ;
    ANTENNADIFFAREA 0.360800 ;
    PORT
      LAYER Metal2 ;
        RECT 222.880 1160.320 223.440 1160.880 ;
    END
  END la_data_out[10]
  PIN la_data_out[11]
    DIRECTION OUTPUT ;
    USE SIGNAL ;
    ANTENNADIFFAREA 0.360800 ;
    PORT
      LAYER Metal3 ;
        RECT 0.000 15.680 0.560 16.240 ;
    END
  END la_data_out[11]
  PIN la_data_out[12]
    DIRECTION OUTPUT ;
    USE SIGNAL ;
    ANTENNADIFFAREA 0.360800 ;
    PORT
      LAYER Metal2 ;
        RECT 89.600 0.000 90.160 0.560 ;
    END
  END la_data_out[12]
  PIN la_data_out[13]
    DIRECTION OUTPUT ;
    USE SIGNAL ;
    ANTENNADIFFAREA 0.360800 ;
    PORT
      LAYER Metal2 ;
        RECT 219.520 1160.320 220.080 1160.880 ;
    END
  END la_data_out[13]
  PIN la_data_out[14]
    DIRECTION OUTPUT ;
    USE SIGNAL ;
    ANTENNADIFFAREA 0.360800 ;
    PORT
      LAYER Metal2 ;
        RECT 552.160 0.000 552.720 0.560 ;
    END
  END la_data_out[14]
  PIN la_data_out[15]
    DIRECTION OUTPUT ;
    USE SIGNAL ;
    ANTENNADIFFAREA 0.360800 ;
    PORT
      LAYER Metal3 ;
        RECT 0.000 5.600 0.560 6.160 ;
    END
  END la_data_out[15]
  PIN la_data_out[16]
    DIRECTION OUTPUT ;
    USE SIGNAL ;
    ANTENNADIFFAREA 0.360800 ;
    PORT
      LAYER Metal2 ;
        RECT 263.200 0.000 263.760 0.560 ;
    END
  END la_data_out[16]
  PIN la_data_out[17]
    DIRECTION OUTPUT ;
    USE SIGNAL ;
    ANTENNADIFFAREA 0.360800 ;
    PORT
      LAYER Metal2 ;
        RECT 865.760 1160.320 866.320 1160.880 ;
    END
  END la_data_out[17]
  PIN la_data_out[18]
    DIRECTION OUTPUT ;
    USE SIGNAL ;
    ANTENNADIFFAREA 0.360800 ;
    PORT
      LAYER Metal2 ;
        RECT 5.600 1160.320 6.160 1160.880 ;
    END
  END la_data_out[18]
  PIN la_data_out[19]
    DIRECTION OUTPUT ;
    USE SIGNAL ;
    ANTENNADIFFAREA 0.360800 ;
    PORT
      LAYER Metal2 ;
        RECT 12.320 1160.320 12.880 1160.880 ;
    END
  END la_data_out[19]
  PIN la_data_out[1]
    DIRECTION OUTPUT ;
    USE SIGNAL ;
    ANTENNADIFFAREA 0.360800 ;
    PORT
      LAYER Metal2 ;
        RECT 228.480 0.000 229.040 0.560 ;
    END
  END la_data_out[1]
  PIN la_data_out[20]
    DIRECTION OUTPUT ;
    USE SIGNAL ;
    ANTENNADIFFAREA 0.360800 ;
    PORT
      LAYER Metal2 ;
        RECT 911.680 1160.320 912.240 1160.880 ;
    END
  END la_data_out[20]
  PIN la_data_out[21]
    DIRECTION OUTPUT ;
    USE SIGNAL ;
    ANTENNADIFFAREA 0.360800 ;
    PORT
      LAYER Metal2 ;
        RECT 297.920 1160.320 298.480 1160.880 ;
    END
  END la_data_out[21]
  PIN la_data_out[22]
    DIRECTION OUTPUT ;
    USE SIGNAL ;
    ANTENNADIFFAREA 0.360800 ;
    PORT
      LAYER Metal2 ;
        RECT 224.000 1160.320 224.560 1160.880 ;
    END
  END la_data_out[22]
  PIN la_data_out[23]
    DIRECTION OUTPUT ;
    USE SIGNAL ;
    ANTENNADIFFAREA 0.360800 ;
    PORT
      LAYER Metal3 ;
        RECT 1142.400 76.160 1142.960 76.720 ;
    END
  END la_data_out[23]
  PIN la_data_out[24]
    DIRECTION OUTPUT ;
    USE SIGNAL ;
    ANTENNADIFFAREA 0.360800 ;
    PORT
      LAYER Metal2 ;
        RECT 378.560 0.000 379.120 0.560 ;
    END
  END la_data_out[24]
  PIN la_data_out[25]
    DIRECTION OUTPUT ;
    USE SIGNAL ;
    ANTENNADIFFAREA 0.360800 ;
    PORT
      LAYER Metal3 ;
        RECT 0.000 4.480 0.560 5.040 ;
    END
  END la_data_out[25]
  PIN la_data_out[26]
    DIRECTION OUTPUT ;
    USE SIGNAL ;
    ANTENNADIFFAREA 0.360800 ;
    PORT
      LAYER Metal2 ;
        RECT 841.120 1160.320 841.680 1160.880 ;
    END
  END la_data_out[26]
  PIN la_data_out[27]
    DIRECTION OUTPUT ;
    USE SIGNAL ;
    ANTENNADIFFAREA 0.360800 ;
    PORT
      LAYER Metal2 ;
        RECT 283.360 1160.320 283.920 1160.880 ;
    END
  END la_data_out[27]
  PIN la_data_out[28]
    DIRECTION OUTPUT ;
    USE SIGNAL ;
    ANTENNADIFFAREA 0.360800 ;
    PORT
      LAYER Metal3 ;
        RECT 0.000 14.560 0.560 15.120 ;
    END
  END la_data_out[28]
  PIN la_data_out[29]
    DIRECTION OUTPUT ;
    USE SIGNAL ;
    ANTENNADIFFAREA 0.360800 ;
    PORT
      LAYER Metal2 ;
        RECT 249.760 1160.320 250.320 1160.880 ;
    END
  END la_data_out[29]
  PIN la_data_out[2]
    DIRECTION OUTPUT ;
    USE SIGNAL ;
    ANTENNADIFFAREA 0.360800 ;
    PORT
      LAYER Metal2 ;
        RECT 6.720 1160.320 7.280 1160.880 ;
    END
  END la_data_out[2]
  PIN la_data_out[30]
    DIRECTION OUTPUT ;
    USE SIGNAL ;
    ANTENNADIFFAREA 0.360800 ;
    PORT
      LAYER Metal2 ;
        RECT 471.520 0.000 472.080 0.560 ;
    END
  END la_data_out[30]
  PIN la_data_out[31]
    DIRECTION OUTPUT ;
    USE SIGNAL ;
    ANTENNADIFFAREA 0.360800 ;
    PORT
      LAYER Metal2 ;
        RECT 184.800 0.000 185.360 0.560 ;
    END
  END la_data_out[31]
  PIN la_data_out[32]
    DIRECTION OUTPUT ;
    USE SIGNAL ;
    ANTENNADIFFAREA 0.360800 ;
    PORT
      LAYER Metal3 ;
        RECT 0.000 12.320 0.560 12.880 ;
    END
  END la_data_out[32]
  PIN la_data_out[33]
    DIRECTION OUTPUT ;
    USE SIGNAL ;
    ANTENNADIFFAREA 0.360800 ;
    PORT
      LAYER Metal2 ;
        RECT 19.040 1160.320 19.600 1160.880 ;
    END
  END la_data_out[33]
  PIN la_data_out[34]
    DIRECTION OUTPUT ;
    USE SIGNAL ;
    ANTENNADIFFAREA 0.360800 ;
    PORT
      LAYER Metal3 ;
        RECT 0.000 957.600 0.560 958.160 ;
    END
  END la_data_out[34]
  PIN la_data_out[35]
    DIRECTION OUTPUT ;
    USE SIGNAL ;
    ANTENNADIFFAREA 0.360800 ;
    PORT
      LAYER Metal3 ;
        RECT 0.000 25.760 0.560 26.320 ;
    END
  END la_data_out[35]
  PIN la_data_out[36]
    DIRECTION OUTPUT ;
    USE SIGNAL ;
    ANTENNADIFFAREA 0.360800 ;
    PORT
      LAYER Metal2 ;
        RECT 512.960 0.000 513.520 0.560 ;
    END
  END la_data_out[36]
  PIN la_data_out[37]
    DIRECTION OUTPUT ;
    USE SIGNAL ;
    ANTENNADIFFAREA 0.360800 ;
    PORT
      LAYER Metal3 ;
        RECT 0.000 13.440 0.560 14.000 ;
    END
  END la_data_out[37]
  PIN la_data_out[38]
    DIRECTION OUTPUT ;
    USE SIGNAL ;
    ANTENNADIFFAREA 0.360800 ;
    PORT
      LAYER Metal2 ;
        RECT 1006.880 1160.320 1007.440 1160.880 ;
    END
  END la_data_out[38]
  PIN la_data_out[39]
    DIRECTION OUTPUT ;
    USE SIGNAL ;
    ANTENNADIFFAREA 0.360800 ;
    PORT
      LAYER Metal3 ;
        RECT 0.000 34.720 0.560 35.280 ;
    END
  END la_data_out[39]
  PIN la_data_out[3]
    DIRECTION OUTPUT ;
    USE SIGNAL ;
    ANTENNADIFFAREA 0.360800 ;
    PORT
      LAYER Metal2 ;
        RECT 344.960 0.000 345.520 0.560 ;
    END
  END la_data_out[3]
  PIN la_data_out[40]
    DIRECTION OUTPUT ;
    USE SIGNAL ;
    ANTENNADIFFAREA 0.360800 ;
    PORT
      LAYER Metal3 ;
        RECT 0.000 36.960 0.560 37.520 ;
    END
  END la_data_out[40]
  PIN la_data_out[41]
    DIRECTION OUTPUT ;
    USE SIGNAL ;
    ANTENNADIFFAREA 0.360800 ;
    PORT
      LAYER Metal3 ;
        RECT 0.000 91.840 0.560 92.400 ;
    END
  END la_data_out[41]
  PIN la_data_out[42]
    DIRECTION OUTPUT ;
    USE SIGNAL ;
    ANTENNADIFFAREA 0.360800 ;
    PORT
      LAYER Metal3 ;
        RECT 0.000 33.600 0.560 34.160 ;
    END
  END la_data_out[42]
  PIN la_data_out[43]
    DIRECTION OUTPUT ;
    USE SIGNAL ;
    ANTENNADIFFAREA 0.360800 ;
    PORT
      LAYER Metal2 ;
        RECT 134.400 1160.320 134.960 1160.880 ;
    END
  END la_data_out[43]
  PIN la_data_out[44]
    DIRECTION OUTPUT ;
    USE SIGNAL ;
    ANTENNADIFFAREA 0.360800 ;
    PORT
      LAYER Metal2 ;
        RECT 551.040 0.000 551.600 0.560 ;
    END
  END la_data_out[44]
  PIN la_data_out[45]
    DIRECTION OUTPUT ;
    USE SIGNAL ;
    ANTENNADIFFAREA 0.360800 ;
    PORT
      LAYER Metal3 ;
        RECT 0.000 94.080 0.560 94.640 ;
    END
  END la_data_out[45]
  PIN la_data_out[46]
    DIRECTION OUTPUT ;
    USE SIGNAL ;
    ANTENNADIFFAREA 0.360800 ;
    PORT
      LAYER Metal3 ;
        RECT 0.000 6.720 0.560 7.280 ;
    END
  END la_data_out[46]
  PIN la_data_out[47]
    DIRECTION OUTPUT ;
    USE SIGNAL ;
    ANTENNADIFFAREA 0.360800 ;
    PORT
      LAYER Metal3 ;
        RECT 0.000 23.520 0.560 24.080 ;
    END
  END la_data_out[47]
  PIN la_data_out[48]
    DIRECTION OUTPUT ;
    USE SIGNAL ;
    ANTENNADIFFAREA 0.360800 ;
    PORT
      LAYER Metal2 ;
        RECT 225.120 1160.320 225.680 1160.880 ;
    END
  END la_data_out[48]
  PIN la_data_out[49]
    DIRECTION OUTPUT ;
    USE SIGNAL ;
    ANTENNADIFFAREA 0.360800 ;
    PORT
      LAYER Metal2 ;
        RECT 8.960 1160.320 9.520 1160.880 ;
    END
  END la_data_out[49]
  PIN la_data_out[4]
    DIRECTION OUTPUT ;
    USE SIGNAL ;
    ANTENNADIFFAREA 0.360800 ;
    PORT
      LAYER Metal3 ;
        RECT 0.000 30.240 0.560 30.800 ;
    END
  END la_data_out[4]
  PIN la_data_out[50]
    DIRECTION OUTPUT ;
    USE SIGNAL ;
    ANTENNADIFFAREA 0.360800 ;
    PORT
      LAYER Metal3 ;
        RECT 0.000 11.200 0.560 11.760 ;
    END
  END la_data_out[50]
  PIN la_data_out[51]
    DIRECTION OUTPUT ;
    USE SIGNAL ;
    ANTENNADIFFAREA 0.360800 ;
    PORT
      LAYER Metal2 ;
        RECT 4.480 1160.320 5.040 1160.880 ;
    END
  END la_data_out[51]
  PIN la_data_out[52]
    DIRECTION OUTPUT ;
    USE SIGNAL ;
    ANTENNADIFFAREA 0.360800 ;
    PORT
      LAYER Metal2 ;
        RECT 264.320 0.000 264.880 0.560 ;
    END
  END la_data_out[52]
  PIN la_data_out[53]
    DIRECTION OUTPUT ;
    USE SIGNAL ;
    ANTENNADIFFAREA 0.360800 ;
    PORT
      LAYER Metal3 ;
        RECT 0.000 216.160 0.560 216.720 ;
    END
  END la_data_out[53]
  PIN la_data_out[54]
    DIRECTION OUTPUT ;
    USE SIGNAL ;
    ANTENNADIFFAREA 0.360800 ;
    PORT
      LAYER Metal3 ;
        RECT 0.000 26.880 0.560 27.440 ;
    END
  END la_data_out[54]
  PIN la_data_out[55]
    DIRECTION OUTPUT ;
    USE SIGNAL ;
    ANTENNADIFFAREA 0.360800 ;
    PORT
      LAYER Metal3 ;
        RECT 0.000 39.200 0.560 39.760 ;
    END
  END la_data_out[55]
  PIN la_data_out[56]
    DIRECTION OUTPUT ;
    USE SIGNAL ;
    ANTENNADIFFAREA 0.360800 ;
    PORT
      LAYER Metal2 ;
        RECT 187.040 1160.320 187.600 1160.880 ;
    END
  END la_data_out[56]
  PIN la_data_out[57]
    DIRECTION OUTPUT ;
    USE SIGNAL ;
    ANTENNADIFFAREA 0.360800 ;
    PORT
      LAYER Metal2 ;
        RECT 463.680 0.000 464.240 0.560 ;
    END
  END la_data_out[57]
  PIN la_data_out[58]
    DIRECTION OUTPUT ;
    USE SIGNAL ;
    ANTENNADIFFAREA 0.360800 ;
    PORT
      LAYER Metal3 ;
        RECT 0.000 995.680 0.560 996.240 ;
    END
  END la_data_out[58]
  PIN la_data_out[59]
    DIRECTION OUTPUT ;
    USE SIGNAL ;
    ANTENNADIFFAREA 0.360800 ;
    PORT
      LAYER Metal3 ;
        RECT 0.000 1079.680 0.560 1080.240 ;
    END
  END la_data_out[59]
  PIN la_data_out[5]
    DIRECTION OUTPUT ;
    USE SIGNAL ;
    ANTENNADIFFAREA 0.360800 ;
    PORT
      LAYER Metal2 ;
        RECT 309.120 1160.320 309.680 1160.880 ;
    END
  END la_data_out[5]
  PIN la_data_out[60]
    DIRECTION OUTPUT ;
    USE SIGNAL ;
    ANTENNADIFFAREA 0.360800 ;
    PORT
      LAYER Metal2 ;
        RECT 138.880 1160.320 139.440 1160.880 ;
    END
  END la_data_out[60]
  PIN la_data_out[61]
    DIRECTION OUTPUT ;
    USE SIGNAL ;
    ANTENNADIFFAREA 0.360800 ;
    PORT
      LAYER Metal2 ;
        RECT 337.120 0.000 337.680 0.560 ;
    END
  END la_data_out[61]
  PIN la_data_out[62]
    DIRECTION OUTPUT ;
    USE SIGNAL ;
    ANTENNADIFFAREA 0.360800 ;
    PORT
      LAYER Metal3 ;
        RECT 0.000 21.280 0.560 21.840 ;
    END
  END la_data_out[62]
  PIN la_data_out[63]
    DIRECTION OUTPUT ;
    USE SIGNAL ;
    ANTENNADIFFAREA 0.360800 ;
    PORT
      LAYER Metal2 ;
        RECT 285.600 1160.320 286.160 1160.880 ;
    END
  END la_data_out[63]
  PIN la_data_out[6]
    DIRECTION OUTPUT ;
    USE SIGNAL ;
    ANTENNADIFFAREA 0.360800 ;
    PORT
      LAYER Metal3 ;
        RECT 0.000 1078.560 0.560 1079.120 ;
    END
  END la_data_out[6]
  PIN la_data_out[7]
    DIRECTION OUTPUT ;
    USE SIGNAL ;
    ANTENNADIFFAREA 0.360800 ;
    PORT
      LAYER Metal3 ;
        RECT 0.000 16.800 0.560 17.360 ;
    END
  END la_data_out[7]
  PIN la_data_out[8]
    DIRECTION OUTPUT ;
    USE SIGNAL ;
    ANTENNADIFFAREA 0.360800 ;
    PORT
      LAYER Metal2 ;
        RECT 181.440 1160.320 182.000 1160.880 ;
    END
  END la_data_out[8]
  PIN la_data_out[9]
    DIRECTION OUTPUT ;
    USE SIGNAL ;
    ANTENNADIFFAREA 0.360800 ;
    PORT
      LAYER Metal2 ;
        RECT 189.280 1160.320 189.840 1160.880 ;
    END
  END la_data_out[9]
  PIN la_oenb[0]
    DIRECTION INPUT ;
    USE SIGNAL ;
    PORT
      LAYER Metal2 ;
        RECT 117.600 0.000 118.160 0.560 ;
    END
  END la_oenb[0]
  PIN la_oenb[10]
    DIRECTION INPUT ;
    USE SIGNAL ;
    PORT
      LAYER Metal2 ;
        RECT 124.320 0.000 124.880 0.560 ;
    END
  END la_oenb[10]
  PIN la_oenb[11]
    DIRECTION INPUT ;
    USE SIGNAL ;
    PORT
      LAYER Metal2 ;
        RECT 119.840 0.000 120.400 0.560 ;
    END
  END la_oenb[11]
  PIN la_oenb[12]
    DIRECTION INPUT ;
    USE SIGNAL ;
    PORT
      LAYER Metal2 ;
        RECT 118.720 0.000 119.280 0.560 ;
    END
  END la_oenb[12]
  PIN la_oenb[13]
    DIRECTION INPUT ;
    USE SIGNAL ;
    PORT
      LAYER Metal2 ;
        RECT 122.080 0.000 122.640 0.560 ;
    END
  END la_oenb[13]
  PIN la_oenb[14]
    DIRECTION INPUT ;
    USE SIGNAL ;
    PORT
      LAYER Metal2 ;
        RECT 120.960 0.000 121.520 0.560 ;
    END
  END la_oenb[14]
  PIN la_oenb[15]
    DIRECTION INPUT ;
    USE SIGNAL ;
    PORT
      LAYER Metal2 ;
        RECT 129.920 0.000 130.480 0.560 ;
    END
  END la_oenb[15]
  PIN la_oenb[16]
    DIRECTION INPUT ;
    USE SIGNAL ;
    PORT
      LAYER Metal2 ;
        RECT 127.680 0.000 128.240 0.560 ;
    END
  END la_oenb[16]
  PIN la_oenb[17]
    DIRECTION INPUT ;
    USE SIGNAL ;
    PORT
      LAYER Metal2 ;
        RECT 126.560 0.000 127.120 0.560 ;
    END
  END la_oenb[17]
  PIN la_oenb[18]
    DIRECTION INPUT ;
    USE SIGNAL ;
    PORT
      LAYER Metal2 ;
        RECT 125.440 0.000 126.000 0.560 ;
    END
  END la_oenb[18]
  PIN la_oenb[19]
    DIRECTION INPUT ;
    USE SIGNAL ;
    PORT
      LAYER Metal2 ;
        RECT 128.800 0.000 129.360 0.560 ;
    END
  END la_oenb[19]
  PIN la_oenb[1]
    DIRECTION INPUT ;
    USE SIGNAL ;
    PORT
      LAYER Metal2 ;
        RECT 132.160 0.000 132.720 0.560 ;
    END
  END la_oenb[1]
  PIN la_oenb[20]
    DIRECTION INPUT ;
    USE SIGNAL ;
    PORT
      LAYER Metal2 ;
        RECT 131.040 0.000 131.600 0.560 ;
    END
  END la_oenb[20]
  PIN la_oenb[21]
    DIRECTION INPUT ;
    USE SIGNAL ;
    PORT
      LAYER Metal2 ;
        RECT 137.760 0.000 138.320 0.560 ;
    END
  END la_oenb[21]
  PIN la_oenb[22]
    DIRECTION INPUT ;
    USE SIGNAL ;
    PORT
      LAYER Metal2 ;
        RECT 133.280 0.000 133.840 0.560 ;
    END
  END la_oenb[22]
  PIN la_oenb[23]
    DIRECTION INPUT ;
    USE SIGNAL ;
    PORT
      LAYER Metal2 ;
        RECT 136.640 0.000 137.200 0.560 ;
    END
  END la_oenb[23]
  PIN la_oenb[24]
    DIRECTION INPUT ;
    USE SIGNAL ;
    PORT
      LAYER Metal2 ;
        RECT 135.520 0.000 136.080 0.560 ;
    END
  END la_oenb[24]
  PIN la_oenb[25]
    DIRECTION INPUT ;
    USE SIGNAL ;
    PORT
      LAYER Metal2 ;
        RECT 134.400 0.000 134.960 0.560 ;
    END
  END la_oenb[25]
  PIN la_oenb[26]
    DIRECTION INPUT ;
    USE SIGNAL ;
    PORT
      LAYER Metal2 ;
        RECT 143.360 0.000 143.920 0.560 ;
    END
  END la_oenb[26]
  PIN la_oenb[27]
    DIRECTION INPUT ;
    USE SIGNAL ;
    PORT
      LAYER Metal2 ;
        RECT 141.120 0.000 141.680 0.560 ;
    END
  END la_oenb[27]
  PIN la_oenb[28]
    DIRECTION INPUT ;
    USE SIGNAL ;
    PORT
      LAYER Metal2 ;
        RECT 140.000 0.000 140.560 0.560 ;
    END
  END la_oenb[28]
  PIN la_oenb[29]
    DIRECTION INPUT ;
    USE SIGNAL ;
    PORT
      LAYER Metal2 ;
        RECT 1.120 0.000 1.680 0.560 ;
    END
  END la_oenb[29]
  PIN la_oenb[2]
    DIRECTION INPUT ;
    USE SIGNAL ;
    PORT
      LAYER Metal2 ;
        RECT 142.240 0.000 142.800 0.560 ;
    END
  END la_oenb[2]
  PIN la_oenb[30]
    DIRECTION INPUT ;
    USE SIGNAL ;
    PORT
      LAYER Metal2 ;
        RECT 145.600 0.000 146.160 0.560 ;
    END
  END la_oenb[30]
  PIN la_oenb[31]
    DIRECTION INPUT ;
    USE SIGNAL ;
    PORT
      LAYER Metal2 ;
        RECT 144.480 0.000 145.040 0.560 ;
    END
  END la_oenb[31]
  PIN la_oenb[32]
    DIRECTION INPUT ;
    USE SIGNAL ;
    PORT
      LAYER Metal2 ;
        RECT 151.200 0.000 151.760 0.560 ;
    END
  END la_oenb[32]
  PIN la_oenb[33]
    DIRECTION INPUT ;
    USE SIGNAL ;
    PORT
      LAYER Metal2 ;
        RECT 146.720 0.000 147.280 0.560 ;
    END
  END la_oenb[33]
  PIN la_oenb[34]
    DIRECTION INPUT ;
    USE SIGNAL ;
    PORT
      LAYER Metal2 ;
        RECT 150.080 0.000 150.640 0.560 ;
    END
  END la_oenb[34]
  PIN la_oenb[35]
    DIRECTION INPUT ;
    USE SIGNAL ;
    PORT
      LAYER Metal2 ;
        RECT 148.960 0.000 149.520 0.560 ;
    END
  END la_oenb[35]
  PIN la_oenb[36]
    DIRECTION INPUT ;
    USE SIGNAL ;
    PORT
      LAYER Metal2 ;
        RECT 147.840 0.000 148.400 0.560 ;
    END
  END la_oenb[36]
  PIN la_oenb[37]
    DIRECTION INPUT ;
    USE SIGNAL ;
    PORT
      LAYER Metal2 ;
        RECT 156.800 0.000 157.360 0.560 ;
    END
  END la_oenb[37]
  PIN la_oenb[38]
    DIRECTION INPUT ;
    USE SIGNAL ;
    PORT
      LAYER Metal2 ;
        RECT 154.560 0.000 155.120 0.560 ;
    END
  END la_oenb[38]
  PIN la_oenb[39]
    DIRECTION INPUT ;
    USE SIGNAL ;
    PORT
      LAYER Metal2 ;
        RECT 153.440 0.000 154.000 0.560 ;
    END
  END la_oenb[39]
  PIN la_oenb[3]
    DIRECTION INPUT ;
    USE SIGNAL ;
    PORT
      LAYER Metal2 ;
        RECT 152.320 0.000 152.880 0.560 ;
    END
  END la_oenb[3]
  PIN la_oenb[40]
    DIRECTION INPUT ;
    USE SIGNAL ;
    PORT
      LAYER Metal2 ;
        RECT 155.680 0.000 156.240 0.560 ;
    END
  END la_oenb[40]
  PIN la_oenb[41]
    DIRECTION INPUT ;
    USE SIGNAL ;
    PORT
      LAYER Metal2 ;
        RECT 159.040 0.000 159.600 0.560 ;
    END
  END la_oenb[41]
  PIN la_oenb[42]
    DIRECTION INPUT ;
    USE SIGNAL ;
    PORT
      LAYER Metal2 ;
        RECT 157.920 0.000 158.480 0.560 ;
    END
  END la_oenb[42]
  PIN la_oenb[43]
    DIRECTION INPUT ;
    USE SIGNAL ;
    PORT
      LAYER Metal2 ;
        RECT 164.640 0.000 165.200 0.560 ;
    END
  END la_oenb[43]
  PIN la_oenb[44]
    DIRECTION INPUT ;
    USE SIGNAL ;
    PORT
      LAYER Metal2 ;
        RECT 160.160 0.000 160.720 0.560 ;
    END
  END la_oenb[44]
  PIN la_oenb[45]
    DIRECTION INPUT ;
    USE SIGNAL ;
    PORT
      LAYER Metal2 ;
        RECT 163.520 0.000 164.080 0.560 ;
    END
  END la_oenb[45]
  PIN la_oenb[46]
    DIRECTION INPUT ;
    USE SIGNAL ;
    PORT
      LAYER Metal2 ;
        RECT 162.400 0.000 162.960 0.560 ;
    END
  END la_oenb[46]
  PIN la_oenb[47]
    DIRECTION INPUT ;
    USE SIGNAL ;
    PORT
      LAYER Metal2 ;
        RECT 161.280 0.000 161.840 0.560 ;
    END
  END la_oenb[47]
  PIN la_oenb[48]
    DIRECTION INPUT ;
    USE SIGNAL ;
    PORT
      LAYER Metal2 ;
        RECT 170.240 0.000 170.800 0.560 ;
    END
  END la_oenb[48]
  PIN la_oenb[49]
    DIRECTION INPUT ;
    USE SIGNAL ;
    PORT
      LAYER Metal2 ;
        RECT 168.000 0.000 168.560 0.560 ;
    END
  END la_oenb[49]
  PIN la_oenb[4]
    DIRECTION INPUT ;
    USE SIGNAL ;
    PORT
      LAYER Metal2 ;
        RECT 166.880 0.000 167.440 0.560 ;
    END
  END la_oenb[4]
  PIN la_oenb[50]
    DIRECTION INPUT ;
    USE SIGNAL ;
    PORT
      LAYER Metal2 ;
        RECT 165.760 0.000 166.320 0.560 ;
    END
  END la_oenb[50]
  PIN la_oenb[51]
    DIRECTION INPUT ;
    USE SIGNAL ;
    PORT
      LAYER Metal2 ;
        RECT 169.120 0.000 169.680 0.560 ;
    END
  END la_oenb[51]
  PIN la_oenb[52]
    DIRECTION INPUT ;
    USE SIGNAL ;
    PORT
      LAYER Metal2 ;
        RECT 172.480 0.000 173.040 0.560 ;
    END
  END la_oenb[52]
  PIN la_oenb[53]
    DIRECTION INPUT ;
    USE SIGNAL ;
    PORT
      LAYER Metal2 ;
        RECT 171.360 0.000 171.920 0.560 ;
    END
  END la_oenb[53]
  PIN la_oenb[54]
    DIRECTION INPUT ;
    USE SIGNAL ;
    PORT
      LAYER Metal2 ;
        RECT 2.240 0.000 2.800 0.560 ;
    END
  END la_oenb[54]
  PIN la_oenb[55]
    DIRECTION INPUT ;
    USE SIGNAL ;
    PORT
      LAYER Metal2 ;
        RECT 173.600 0.000 174.160 0.560 ;
    END
  END la_oenb[55]
  PIN la_oenb[56]
    DIRECTION INPUT ;
    USE SIGNAL ;
    PORT
      LAYER Metal2 ;
        RECT 176.960 0.000 177.520 0.560 ;
    END
  END la_oenb[56]
  PIN la_oenb[57]
    DIRECTION INPUT ;
    USE SIGNAL ;
    PORT
      LAYER Metal2 ;
        RECT 175.840 0.000 176.400 0.560 ;
    END
  END la_oenb[57]
  PIN la_oenb[58]
    DIRECTION INPUT ;
    USE SIGNAL ;
    PORT
      LAYER Metal2 ;
        RECT 174.720 0.000 175.280 0.560 ;
    END
  END la_oenb[58]
  PIN la_oenb[59]
    DIRECTION INPUT ;
    USE SIGNAL ;
    PORT
      LAYER Metal2 ;
        RECT 183.680 0.000 184.240 0.560 ;
    END
  END la_oenb[59]
  PIN la_oenb[5]
    DIRECTION INPUT ;
    USE SIGNAL ;
    PORT
      LAYER Metal2 ;
        RECT 181.440 0.000 182.000 0.560 ;
    END
  END la_oenb[5]
  PIN la_oenb[60]
    DIRECTION INPUT ;
    USE SIGNAL ;
    PORT
      LAYER Metal2 ;
        RECT 180.320 0.000 180.880 0.560 ;
    END
  END la_oenb[60]
  PIN la_oenb[61]
    DIRECTION INPUT ;
    USE SIGNAL ;
    PORT
      LAYER Metal2 ;
        RECT 179.200 0.000 179.760 0.560 ;
    END
  END la_oenb[61]
  PIN la_oenb[62]
    DIRECTION INPUT ;
    USE SIGNAL ;
    PORT
      LAYER Metal2 ;
        RECT 182.560 0.000 183.120 0.560 ;
    END
  END la_oenb[62]
  PIN la_oenb[63]
    DIRECTION INPUT ;
    USE SIGNAL ;
    PORT
      LAYER Metal2 ;
        RECT 185.920 0.000 186.480 0.560 ;
    END
  END la_oenb[63]
  PIN la_oenb[6]
    DIRECTION INPUT ;
    USE SIGNAL ;
    PORT
      LAYER Metal2 ;
        RECT 11.200 0.000 11.760 0.560 ;
    END
  END la_oenb[6]
  PIN la_oenb[7]
    DIRECTION INPUT ;
    USE SIGNAL ;
    PORT
      LAYER Metal2 ;
        RECT 191.520 0.000 192.080 0.560 ;
    END
  END la_oenb[7]
  PIN la_oenb[8]
    DIRECTION INPUT ;
    USE SIGNAL ;
    PORT
      LAYER Metal2 ;
        RECT 187.040 0.000 187.600 0.560 ;
    END
  END la_oenb[8]
  PIN la_oenb[9]
    DIRECTION INPUT ;
    USE SIGNAL ;
    PORT
      LAYER Metal2 ;
        RECT 190.400 0.000 190.960 0.560 ;
    END
  END la_oenb[9]
  PIN vdd
    DIRECTION INOUT ;
    USE POWER ;
    PORT
      LAYER Metal4 ;
        RECT 22.240 15.380 23.840 1144.940 ;
    END
    PORT
      LAYER Metal4 ;
        RECT 175.840 15.380 177.440 1144.940 ;
    END
    PORT
      LAYER Metal4 ;
        RECT 329.440 15.380 331.040 1144.940 ;
    END
    PORT
      LAYER Metal4 ;
        RECT 483.040 15.380 484.640 1144.940 ;
    END
    PORT
      LAYER Metal4 ;
        RECT 636.640 15.380 638.240 1144.940 ;
    END
    PORT
      LAYER Metal4 ;
        RECT 790.240 15.380 791.840 1144.940 ;
    END
    PORT
      LAYER Metal4 ;
        RECT 943.840 15.380 945.440 1144.940 ;
    END
    PORT
      LAYER Metal4 ;
        RECT 1097.440 15.380 1099.040 1144.940 ;
    END
  END vdd
  PIN vss
    DIRECTION INOUT ;
    USE GROUND ;
    PORT
      LAYER Metal4 ;
        RECT 25.540 15.380 27.140 1144.940 ;
    END
    PORT
      LAYER Metal4 ;
        RECT 179.140 15.380 180.740 1144.940 ;
    END
    PORT
      LAYER Metal4 ;
        RECT 332.740 15.380 334.340 1144.940 ;
    END
    PORT
      LAYER Metal4 ;
        RECT 486.340 15.380 487.940 1144.940 ;
    END
    PORT
      LAYER Metal4 ;
        RECT 639.940 15.380 641.540 1144.940 ;
    END
    PORT
      LAYER Metal4 ;
        RECT 793.540 15.380 795.140 1144.940 ;
    END
    PORT
      LAYER Metal4 ;
        RECT 947.140 15.380 948.740 1144.940 ;
    END
    PORT
      LAYER Metal4 ;
        RECT 1100.740 15.380 1102.340 1144.940 ;
    END
  END vss
  PIN wb_clk_i
    DIRECTION INPUT ;
    USE SIGNAL ;
    ANTENNAGATEAREA 4.738000 ;
    PORT
      LAYER Metal3 ;
        RECT 0.000 935.200 0.560 935.760 ;
    END
  END wb_clk_i
  PIN wb_rst_i
    DIRECTION INPUT ;
    USE SIGNAL ;
    PORT
      LAYER Metal2 ;
        RECT 189.280 0.000 189.840 0.560 ;
    END
  END wb_rst_i
  PIN wbs_ack_o
    DIRECTION OUTPUT ;
    USE SIGNAL ;
    ANTENNADIFFAREA 1.182800 ;
    PORT
      LAYER Metal2 ;
        RECT 682.080 0.000 682.640 0.560 ;
    END
  END wbs_ack_o
  PIN wbs_adr_i[0]
    DIRECTION INPUT ;
    USE SIGNAL ;
    PORT
      LAYER Metal2 ;
        RECT 188.160 0.000 188.720 0.560 ;
    END
  END wbs_adr_i[0]
  PIN wbs_adr_i[10]
    DIRECTION INPUT ;
    USE SIGNAL ;
    PORT
      LAYER Metal2 ;
        RECT 197.120 0.000 197.680 0.560 ;
    END
  END wbs_adr_i[10]
  PIN wbs_adr_i[11]
    DIRECTION INPUT ;
    USE SIGNAL ;
    PORT
      LAYER Metal2 ;
        RECT 194.880 0.000 195.440 0.560 ;
    END
  END wbs_adr_i[11]
  PIN wbs_adr_i[12]
    DIRECTION INPUT ;
    USE SIGNAL ;
    PORT
      LAYER Metal2 ;
        RECT 193.760 0.000 194.320 0.560 ;
    END
  END wbs_adr_i[12]
  PIN wbs_adr_i[13]
    DIRECTION INPUT ;
    USE SIGNAL ;
    PORT
      LAYER Metal2 ;
        RECT 192.640 0.000 193.200 0.560 ;
    END
  END wbs_adr_i[13]
  PIN wbs_adr_i[14]
    DIRECTION INPUT ;
    USE SIGNAL ;
    PORT
      LAYER Metal2 ;
        RECT 196.000 0.000 196.560 0.560 ;
    END
  END wbs_adr_i[14]
  PIN wbs_adr_i[15]
    DIRECTION INPUT ;
    USE SIGNAL ;
    PORT
      LAYER Metal2 ;
        RECT 199.360 0.000 199.920 0.560 ;
    END
  END wbs_adr_i[15]
  PIN wbs_adr_i[16]
    DIRECTION INPUT ;
    USE SIGNAL ;
    PORT
      LAYER Metal2 ;
        RECT 198.240 0.000 198.800 0.560 ;
    END
  END wbs_adr_i[16]
  PIN wbs_adr_i[17]
    DIRECTION INPUT ;
    USE SIGNAL ;
    PORT
      LAYER Metal2 ;
        RECT 204.960 0.000 205.520 0.560 ;
    END
  END wbs_adr_i[17]
  PIN wbs_adr_i[18]
    DIRECTION INPUT ;
    USE SIGNAL ;
    PORT
      LAYER Metal2 ;
        RECT 200.480 0.000 201.040 0.560 ;
    END
  END wbs_adr_i[18]
  PIN wbs_adr_i[19]
    DIRECTION INPUT ;
    USE SIGNAL ;
    PORT
      LAYER Metal2 ;
        RECT 203.840 0.000 204.400 0.560 ;
    END
  END wbs_adr_i[19]
  PIN wbs_adr_i[1]
    DIRECTION INPUT ;
    USE SIGNAL ;
    PORT
      LAYER Metal2 ;
        RECT 202.720 0.000 203.280 0.560 ;
    END
  END wbs_adr_i[1]
  PIN wbs_adr_i[20]
    DIRECTION INPUT ;
    USE SIGNAL ;
    PORT
      LAYER Metal2 ;
        RECT 201.600 0.000 202.160 0.560 ;
    END
  END wbs_adr_i[20]
  PIN wbs_adr_i[21]
    DIRECTION INPUT ;
    USE SIGNAL ;
    PORT
      LAYER Metal2 ;
        RECT 210.560 0.000 211.120 0.560 ;
    END
  END wbs_adr_i[21]
  PIN wbs_adr_i[22]
    DIRECTION INPUT ;
    USE SIGNAL ;
    PORT
      LAYER Metal2 ;
        RECT 208.320 0.000 208.880 0.560 ;
    END
  END wbs_adr_i[22]
  PIN wbs_adr_i[23]
    DIRECTION INPUT ;
    USE SIGNAL ;
    PORT
      LAYER Metal2 ;
        RECT 207.200 0.000 207.760 0.560 ;
    END
  END wbs_adr_i[23]
  PIN wbs_adr_i[24]
    DIRECTION INPUT ;
    USE SIGNAL ;
    PORT
      LAYER Metal2 ;
        RECT 206.080 0.000 206.640 0.560 ;
    END
  END wbs_adr_i[24]
  PIN wbs_adr_i[25]
    DIRECTION INPUT ;
    USE SIGNAL ;
    PORT
      LAYER Metal2 ;
        RECT 209.440 0.000 210.000 0.560 ;
    END
  END wbs_adr_i[25]
  PIN wbs_adr_i[26]
    DIRECTION INPUT ;
    USE SIGNAL ;
    PORT
      LAYER Metal2 ;
        RECT 212.800 0.000 213.360 0.560 ;
    END
  END wbs_adr_i[26]
  PIN wbs_adr_i[27]
    DIRECTION INPUT ;
    USE SIGNAL ;
    PORT
      LAYER Metal2 ;
        RECT 211.680 0.000 212.240 0.560 ;
    END
  END wbs_adr_i[27]
  PIN wbs_adr_i[28]
    DIRECTION INPUT ;
    USE SIGNAL ;
    PORT
      LAYER Metal2 ;
        RECT 219.520 0.000 220.080 0.560 ;
    END
  END wbs_adr_i[28]
  PIN wbs_adr_i[29]
    DIRECTION INPUT ;
    USE SIGNAL ;
    PORT
      LAYER Metal2 ;
        RECT 213.920 0.000 214.480 0.560 ;
    END
  END wbs_adr_i[29]
  PIN wbs_adr_i[2]
    DIRECTION INPUT ;
    USE SIGNAL ;
    ANTENNAGATEAREA 1.102000 ;
    PORT
      LAYER Metal2 ;
        RECT 659.680 0.000 660.240 0.560 ;
    END
  END wbs_adr_i[2]
  PIN wbs_adr_i[30]
    DIRECTION INPUT ;
    USE SIGNAL ;
    PORT
      LAYER Metal2 ;
        RECT 217.280 0.000 217.840 0.560 ;
    END
  END wbs_adr_i[30]
  PIN wbs_adr_i[31]
    DIRECTION INPUT ;
    USE SIGNAL ;
    PORT
      LAYER Metal2 ;
        RECT 3.360 0.000 3.920 0.560 ;
    END
  END wbs_adr_i[31]
  PIN wbs_adr_i[3]
    DIRECTION INPUT ;
    USE SIGNAL ;
    ANTENNAGATEAREA 1.102000 ;
    PORT
      LAYER Metal2 ;
        RECT 657.440 0.000 658.000 0.560 ;
    END
  END wbs_adr_i[3]
  PIN wbs_adr_i[4]
    DIRECTION INPUT ;
    USE SIGNAL ;
    ANTENNAGATEAREA 1.102000 ;
    PORT
      LAYER Metal2 ;
        RECT 683.200 0.000 683.760 0.560 ;
    END
  END wbs_adr_i[4]
  PIN wbs_adr_i[5]
    DIRECTION INPUT ;
    USE SIGNAL ;
    ANTENNAGATEAREA 1.102000 ;
    PORT
      LAYER Metal2 ;
        RECT 684.320 0.000 684.880 0.560 ;
    END
  END wbs_adr_i[5]
  PIN wbs_adr_i[6]
    DIRECTION INPUT ;
    USE SIGNAL ;
    PORT
      LAYER Metal2 ;
        RECT 215.040 0.000 215.600 0.560 ;
    END
  END wbs_adr_i[6]
  PIN wbs_adr_i[7]
    DIRECTION INPUT ;
    USE SIGNAL ;
    PORT
      LAYER Metal2 ;
        RECT 225.120 0.000 225.680 0.560 ;
    END
  END wbs_adr_i[7]
  PIN wbs_adr_i[8]
    DIRECTION INPUT ;
    USE SIGNAL ;
    PORT
      LAYER Metal2 ;
        RECT 226.240 0.000 226.800 0.560 ;
    END
  END wbs_adr_i[8]
  PIN wbs_adr_i[9]
    DIRECTION INPUT ;
    USE SIGNAL ;
    PORT
      LAYER Metal2 ;
        RECT 227.360 0.000 227.920 0.560 ;
    END
  END wbs_adr_i[9]
  PIN wbs_cyc_i
    DIRECTION INPUT ;
    USE SIGNAL ;
    ANTENNAGATEAREA 1.102000 ;
    PORT
      LAYER Metal2 ;
        RECT 655.200 0.000 655.760 0.560 ;
    END
  END wbs_cyc_i
  PIN wbs_dat_i[0]
    DIRECTION INPUT ;
    USE SIGNAL ;
    ANTENNAGATEAREA 1.102000 ;
    PORT
      LAYER Metal2 ;
        RECT 557.760 0.000 558.320 0.560 ;
    END
  END wbs_dat_i[0]
  PIN wbs_dat_i[10]
    DIRECTION INPUT ;
    USE SIGNAL ;
    ANTENNAGATEAREA 1.102000 ;
    PORT
      LAYER Metal3 ;
        RECT 1142.400 464.800 1142.960 465.360 ;
    END
  END wbs_dat_i[10]
  PIN wbs_dat_i[11]
    DIRECTION INPUT ;
    USE SIGNAL ;
    ANTENNAGATEAREA 1.102000 ;
    PORT
      LAYER Metal3 ;
        RECT 0.000 711.200 0.560 711.760 ;
    END
  END wbs_dat_i[11]
  PIN wbs_dat_i[12]
    DIRECTION INPUT ;
    USE SIGNAL ;
    ANTENNAGATEAREA 1.102000 ;
    PORT
      LAYER Metal3 ;
        RECT 0.000 568.960 0.560 569.520 ;
    END
  END wbs_dat_i[12]
  PIN wbs_dat_i[13]
    DIRECTION INPUT ;
    USE SIGNAL ;
    ANTENNAGATEAREA 1.102000 ;
    PORT
      LAYER Metal3 ;
        RECT 0.000 631.680 0.560 632.240 ;
    END
  END wbs_dat_i[13]
  PIN wbs_dat_i[14]
    DIRECTION INPUT ;
    USE SIGNAL ;
    ANTENNAGATEAREA 1.102000 ;
    PORT
      LAYER Metal3 ;
        RECT 0.000 794.080 0.560 794.640 ;
    END
  END wbs_dat_i[14]
  PIN wbs_dat_i[15]
    DIRECTION INPUT ;
    USE SIGNAL ;
    ANTENNAGATEAREA 1.102000 ;
    PORT
      LAYER Metal3 ;
        RECT 0.000 676.480 0.560 677.040 ;
    END
  END wbs_dat_i[15]
  PIN wbs_dat_i[16]
    DIRECTION INPUT ;
    USE SIGNAL ;
    ANTENNAGATEAREA 1.102000 ;
    PORT
      LAYER Metal2 ;
        RECT 537.600 0.000 538.160 0.560 ;
    END
  END wbs_dat_i[16]
  PIN wbs_dat_i[17]
    DIRECTION INPUT ;
    USE SIGNAL ;
    ANTENNAGATEAREA 1.102000 ;
    PORT
      LAYER Metal2 ;
        RECT 657.440 1160.320 658.000 1160.880 ;
    END
  END wbs_dat_i[17]
  PIN wbs_dat_i[18]
    DIRECTION INPUT ;
    USE SIGNAL ;
    ANTENNAGATEAREA 1.102000 ;
    PORT
      LAYER Metal3 ;
        RECT 1142.400 449.120 1142.960 449.680 ;
    END
  END wbs_dat_i[18]
  PIN wbs_dat_i[19]
    DIRECTION INPUT ;
    USE SIGNAL ;
    ANTENNAGATEAREA 1.102000 ;
    PORT
      LAYER Metal3 ;
        RECT 0.000 704.480 0.560 705.040 ;
    END
  END wbs_dat_i[19]
  PIN wbs_dat_i[1]
    DIRECTION INPUT ;
    USE SIGNAL ;
    ANTENNAGATEAREA 1.102000 ;
    PORT
      LAYER Metal2 ;
        RECT 673.120 0.000 673.680 0.560 ;
    END
  END wbs_dat_i[1]
  PIN wbs_dat_i[20]
    DIRECTION INPUT ;
    USE SIGNAL ;
    ANTENNAGATEAREA 1.102000 ;
    PORT
      LAYER Metal3 ;
        RECT 0.000 710.080 0.560 710.640 ;
    END
  END wbs_dat_i[20]
  PIN wbs_dat_i[21]
    DIRECTION INPUT ;
    USE SIGNAL ;
    ANTENNAGATEAREA 1.102000 ;
    PORT
      LAYER Metal3 ;
        RECT 1142.400 482.720 1142.960 483.280 ;
    END
  END wbs_dat_i[21]
  PIN wbs_dat_i[22]
    DIRECTION INPUT ;
    USE SIGNAL ;
    ANTENNAGATEAREA 1.102000 ;
    PORT
      LAYER Metal3 ;
        RECT 0.000 708.960 0.560 709.520 ;
    END
  END wbs_dat_i[22]
  PIN wbs_dat_i[23]
    DIRECTION INPUT ;
    USE SIGNAL ;
    ANTENNAGATEAREA 1.102000 ;
    PORT
      LAYER Metal3 ;
        RECT 0.000 707.840 0.560 708.400 ;
    END
  END wbs_dat_i[23]
  PIN wbs_dat_i[24]
    DIRECTION INPUT ;
    USE SIGNAL ;
    ANTENNAGATEAREA 1.102000 ;
    PORT
      LAYER Metal3 ;
        RECT 1142.400 705.600 1142.960 706.160 ;
    END
  END wbs_dat_i[24]
  PIN wbs_dat_i[25]
    DIRECTION INPUT ;
    USE SIGNAL ;
    ANTENNAGATEAREA 1.102000 ;
    PORT
      LAYER Metal3 ;
        RECT 1142.400 673.120 1142.960 673.680 ;
    END
  END wbs_dat_i[25]
  PIN wbs_dat_i[26]
    DIRECTION INPUT ;
    USE SIGNAL ;
    ANTENNAGATEAREA 1.102000 ;
    PORT
      LAYER Metal2 ;
        RECT 836.640 1160.320 837.200 1160.880 ;
    END
  END wbs_dat_i[26]
  PIN wbs_dat_i[27]
    DIRECTION INPUT ;
    USE SIGNAL ;
    ANTENNAGATEAREA 1.102000 ;
    PORT
      LAYER Metal3 ;
        RECT 1142.400 674.240 1142.960 674.800 ;
    END
  END wbs_dat_i[27]
  PIN wbs_dat_i[28]
    DIRECTION INPUT ;
    USE SIGNAL ;
    ANTENNAGATEAREA 1.102000 ;
    PORT
      LAYER Metal3 ;
        RECT 1142.400 675.360 1142.960 675.920 ;
    END
  END wbs_dat_i[28]
  PIN wbs_dat_i[29]
    DIRECTION INPUT ;
    USE SIGNAL ;
    ANTENNAGATEAREA 1.102000 ;
    PORT
      LAYER Metal3 ;
        RECT 1142.400 676.480 1142.960 677.040 ;
    END
  END wbs_dat_i[29]
  PIN wbs_dat_i[2]
    DIRECTION INPUT ;
    USE SIGNAL ;
    ANTENNAGATEAREA 1.102000 ;
    PORT
      LAYER Metal2 ;
        RECT 674.240 0.000 674.800 0.560 ;
    END
  END wbs_dat_i[2]
  PIN wbs_dat_i[30]
    DIRECTION INPUT ;
    USE SIGNAL ;
    ANTENNAGATEAREA 1.102000 ;
    PORT
      LAYER Metal3 ;
        RECT 1142.400 677.600 1142.960 678.160 ;
    END
  END wbs_dat_i[30]
  PIN wbs_dat_i[31]
    DIRECTION INPUT ;
    USE SIGNAL ;
    ANTENNAGATEAREA 1.102000 ;
    PORT
      LAYER Metal3 ;
        RECT 1142.400 706.720 1142.960 707.280 ;
    END
  END wbs_dat_i[31]
  PIN wbs_dat_i[3]
    DIRECTION INPUT ;
    USE SIGNAL ;
    ANTENNAGATEAREA 1.102000 ;
    PORT
      LAYER Metal2 ;
        RECT 465.920 0.000 466.480 0.560 ;
    END
  END wbs_dat_i[3]
  PIN wbs_dat_i[4]
    DIRECTION INPUT ;
    USE SIGNAL ;
    ANTENNAGATEAREA 1.102000 ;
    PORT
      LAYER Metal2 ;
        RECT 449.120 0.000 449.680 0.560 ;
    END
  END wbs_dat_i[4]
  PIN wbs_dat_i[5]
    DIRECTION INPUT ;
    USE SIGNAL ;
    ANTENNAGATEAREA 1.102000 ;
    PORT
      LAYER Metal2 ;
        RECT 450.240 0.000 450.800 0.560 ;
    END
  END wbs_dat_i[5]
  PIN wbs_dat_i[6]
    DIRECTION INPUT ;
    USE SIGNAL ;
    ANTENNAGATEAREA 1.102000 ;
    PORT
      LAYER Metal2 ;
        RECT 451.360 0.000 451.920 0.560 ;
    END
  END wbs_dat_i[6]
  PIN wbs_dat_i[7]
    DIRECTION INPUT ;
    USE SIGNAL ;
    ANTENNAGATEAREA 1.102000 ;
    PORT
      LAYER Metal2 ;
        RECT 452.480 0.000 453.040 0.560 ;
    END
  END wbs_dat_i[7]
  PIN wbs_dat_i[8]
    DIRECTION INPUT ;
    USE SIGNAL ;
    ANTENNAGATEAREA 1.102000 ;
    PORT
      LAYER Metal3 ;
        RECT 0.000 601.440 0.560 602.000 ;
    END
  END wbs_dat_i[8]
  PIN wbs_dat_i[9]
    DIRECTION INPUT ;
    USE SIGNAL ;
    ANTENNAGATEAREA 1.102000 ;
    PORT
      LAYER Metal2 ;
        RECT 453.600 0.000 454.160 0.560 ;
    END
  END wbs_dat_i[9]
  PIN wbs_dat_o[0]
    DIRECTION OUTPUT ;
    USE SIGNAL ;
    ANTENNADIFFAREA 1.182800 ;
    PORT
      LAYER Metal2 ;
        RECT 730.240 0.000 730.800 0.560 ;
    END
  END wbs_dat_o[0]
  PIN wbs_dat_o[10]
    DIRECTION OUTPUT ;
    USE SIGNAL ;
    ANTENNADIFFAREA 1.182800 ;
    PORT
      LAYER Metal2 ;
        RECT 484.960 0.000 485.520 0.560 ;
    END
  END wbs_dat_o[10]
  PIN wbs_dat_o[11]
    DIRECTION OUTPUT ;
    USE SIGNAL ;
    ANTENNADIFFAREA 1.182800 ;
    PORT
      LAYER Metal2 ;
        RECT 519.680 1160.320 520.240 1160.880 ;
    END
  END wbs_dat_o[11]
  PIN wbs_dat_o[12]
    DIRECTION OUTPUT ;
    USE SIGNAL ;
    ANTENNADIFFAREA 1.182800 ;
    PORT
      LAYER Metal3 ;
        RECT 0.000 532.000 0.560 532.560 ;
    END
  END wbs_dat_o[12]
  PIN wbs_dat_o[13]
    DIRECTION OUTPUT ;
    USE SIGNAL ;
    ANTENNADIFFAREA 1.182800 ;
    PORT
      LAYER Metal3 ;
        RECT 0.000 629.440 0.560 630.000 ;
    END
  END wbs_dat_o[13]
  PIN wbs_dat_o[14]
    DIRECTION OUTPUT ;
    USE SIGNAL ;
    ANTENNADIFFAREA 1.182800 ;
    PORT
      LAYER Metal2 ;
        RECT 518.560 1160.320 519.120 1160.880 ;
    END
  END wbs_dat_o[14]
  PIN wbs_dat_o[15]
    DIRECTION OUTPUT ;
    USE SIGNAL ;
    ANTENNADIFFAREA 1.182800 ;
    PORT
      LAYER Metal3 ;
        RECT 0.000 673.120 0.560 673.680 ;
    END
  END wbs_dat_o[15]
  PIN wbs_dat_o[16]
    DIRECTION OUTPUT ;
    USE SIGNAL ;
    ANTENNADIFFAREA 1.182800 ;
    PORT
      LAYER Metal2 ;
        RECT 564.480 0.000 565.040 0.560 ;
    END
  END wbs_dat_o[16]
  PIN wbs_dat_o[17]
    DIRECTION OUTPUT ;
    USE SIGNAL ;
    ANTENNADIFFAREA 1.182800 ;
    PORT
      LAYER Metal2 ;
        RECT 639.520 0.000 640.080 0.560 ;
    END
  END wbs_dat_o[17]
  PIN wbs_dat_o[18]
    DIRECTION OUTPUT ;
    USE SIGNAL ;
    ANTENNADIFFAREA 1.182800 ;
    PORT
      LAYER Metal3 ;
        RECT 1142.400 563.360 1142.960 563.920 ;
    END
  END wbs_dat_o[18]
  PIN wbs_dat_o[19]
    DIRECTION OUTPUT ;
    USE SIGNAL ;
    ANTENNADIFFAREA 1.182800 ;
    PORT
      LAYER Metal3 ;
        RECT 1142.400 577.920 1142.960 578.480 ;
    END
  END wbs_dat_o[19]
  PIN wbs_dat_o[1]
    DIRECTION OUTPUT ;
    USE SIGNAL ;
    ANTENNADIFFAREA 1.182800 ;
    PORT
      LAYER Metal2 ;
        RECT 688.800 0.000 689.360 0.560 ;
    END
  END wbs_dat_o[1]
  PIN wbs_dat_o[20]
    DIRECTION OUTPUT ;
    USE SIGNAL ;
    ANTENNADIFFAREA 1.182800 ;
    PORT
      LAYER Metal2 ;
        RECT 573.440 1160.320 574.000 1160.880 ;
    END
  END wbs_dat_o[20]
  PIN wbs_dat_o[21]
    DIRECTION OUTPUT ;
    USE SIGNAL ;
    ANTENNADIFFAREA 1.182800 ;
    PORT
      LAYER Metal3 ;
        RECT 1142.400 694.400 1142.960 694.960 ;
    END
  END wbs_dat_o[21]
  PIN wbs_dat_o[22]
    DIRECTION OUTPUT ;
    USE SIGNAL ;
    ANTENNADIFFAREA 1.182800 ;
    PORT
      LAYER Metal3 ;
        RECT 1142.400 633.920 1142.960 634.480 ;
    END
  END wbs_dat_o[22]
  PIN wbs_dat_o[23]
    DIRECTION OUTPUT ;
    USE SIGNAL ;
    ANTENNADIFFAREA 1.182800 ;
    PORT
      LAYER Metal2 ;
        RECT 598.080 0.000 598.640 0.560 ;
    END
  END wbs_dat_o[23]
  PIN wbs_dat_o[24]
    DIRECTION OUTPUT ;
    USE SIGNAL ;
    ANTENNADIFFAREA 1.182800 ;
    PORT
      LAYER Metal2 ;
        RECT 704.480 1160.320 705.040 1160.880 ;
    END
  END wbs_dat_o[24]
  PIN wbs_dat_o[25]
    DIRECTION OUTPUT ;
    USE SIGNAL ;
    ANTENNADIFFAREA 1.182800 ;
    PORT
      LAYER Metal2 ;
        RECT 788.480 1160.320 789.040 1160.880 ;
    END
  END wbs_dat_o[25]
  PIN wbs_dat_o[26]
    DIRECTION OUTPUT ;
    USE SIGNAL ;
    ANTENNADIFFAREA 1.182800 ;
    PORT
      LAYER Metal3 ;
        RECT 1142.400 782.880 1142.960 783.440 ;
    END
  END wbs_dat_o[26]
  PIN wbs_dat_o[27]
    DIRECTION OUTPUT ;
    USE SIGNAL ;
    ANTENNADIFFAREA 1.182800 ;
    PORT
      LAYER Metal3 ;
        RECT 1142.400 744.800 1142.960 745.360 ;
    END
  END wbs_dat_o[27]
  PIN wbs_dat_o[28]
    DIRECTION OUTPUT ;
    USE SIGNAL ;
    ANTENNADIFFAREA 1.182800 ;
    PORT
      LAYER Metal3 ;
        RECT 1142.400 678.720 1142.960 679.280 ;
    END
  END wbs_dat_o[28]
  PIN wbs_dat_o[29]
    DIRECTION OUTPUT ;
    USE SIGNAL ;
    ANTENNADIFFAREA 1.182800 ;
    PORT
      LAYER Metal3 ;
        RECT 1142.400 780.640 1142.960 781.200 ;
    END
  END wbs_dat_o[29]
  PIN wbs_dat_o[2]
    DIRECTION OUTPUT ;
    USE SIGNAL ;
    ANTENNADIFFAREA 1.182800 ;
    PORT
      LAYER Metal2 ;
        RECT 687.680 0.000 688.240 0.560 ;
    END
  END wbs_dat_o[2]
  PIN wbs_dat_o[30]
    DIRECTION OUTPUT ;
    USE SIGNAL ;
    ANTENNADIFFAREA 1.182800 ;
    PORT
      LAYER Metal3 ;
        RECT 1142.400 776.160 1142.960 776.720 ;
    END
  END wbs_dat_o[30]
  PIN wbs_dat_o[31]
    DIRECTION OUTPUT ;
    USE SIGNAL ;
    ANTENNADIFFAREA 1.182800 ;
    PORT
      LAYER Metal3 ;
        RECT 1142.400 725.760 1142.960 726.320 ;
    END
  END wbs_dat_o[31]
  PIN wbs_dat_o[3]
    DIRECTION OUTPUT ;
    USE SIGNAL ;
    ANTENNADIFFAREA 1.182800 ;
    PORT
      LAYER Metal2 ;
        RECT 500.640 0.000 501.200 0.560 ;
    END
  END wbs_dat_o[3]
  PIN wbs_dat_o[4]
    DIRECTION OUTPUT ;
    USE SIGNAL ;
    ANTENNADIFFAREA 1.182800 ;
    PORT
      LAYER Metal2 ;
        RECT 516.320 0.000 516.880 0.560 ;
    END
  END wbs_dat_o[4]
  PIN wbs_dat_o[5]
    DIRECTION OUTPUT ;
    USE SIGNAL ;
    ANTENNADIFFAREA 1.182800 ;
    PORT
      LAYER Metal2 ;
        RECT 542.080 0.000 542.640 0.560 ;
    END
  END wbs_dat_o[5]
  PIN wbs_dat_o[6]
    DIRECTION OUTPUT ;
    USE SIGNAL ;
    ANTENNADIFFAREA 1.182800 ;
    PORT
      LAYER Metal2 ;
        RECT 591.360 0.000 591.920 0.560 ;
    END
  END wbs_dat_o[6]
  PIN wbs_dat_o[7]
    DIRECTION OUTPUT ;
    USE SIGNAL ;
    ANTENNADIFFAREA 1.182800 ;
    PORT
      LAYER Metal2 ;
        RECT 481.600 0.000 482.160 0.560 ;
    END
  END wbs_dat_o[7]
  PIN wbs_dat_o[8]
    DIRECTION OUTPUT ;
    USE SIGNAL ;
    ANTENNADIFFAREA 1.182800 ;
    PORT
      LAYER Metal3 ;
        RECT 0.000 579.040 0.560 579.600 ;
    END
  END wbs_dat_o[8]
  PIN wbs_dat_o[9]
    DIRECTION OUTPUT ;
    USE SIGNAL ;
    ANTENNADIFFAREA 1.182800 ;
    PORT
      LAYER Metal2 ;
        RECT 482.720 0.000 483.280 0.560 ;
    END
  END wbs_dat_o[9]
  PIN wbs_sel_i[0]
    DIRECTION INPUT ;
    USE SIGNAL ;
    PORT
      LAYER Metal2 ;
        RECT 229.600 0.000 230.160 0.560 ;
    END
  END wbs_sel_i[0]
  PIN wbs_sel_i[1]
    DIRECTION INPUT ;
    USE SIGNAL ;
    PORT
      LAYER Metal2 ;
        RECT 230.720 0.000 231.280 0.560 ;
    END
  END wbs_sel_i[1]
  PIN wbs_sel_i[2]
    DIRECTION INPUT ;
    USE SIGNAL ;
    PORT
      LAYER Metal2 ;
        RECT 231.840 0.000 232.400 0.560 ;
    END
  END wbs_sel_i[2]
  PIN wbs_sel_i[3]
    DIRECTION INPUT ;
    USE SIGNAL ;
    PORT
      LAYER Metal2 ;
        RECT 232.960 0.000 233.520 0.560 ;
    END
  END wbs_sel_i[3]
  PIN wbs_stb_i
    DIRECTION INPUT ;
    USE SIGNAL ;
    ANTENNAGATEAREA 1.102000 ;
    PORT
      LAYER Metal2 ;
        RECT 656.320 0.000 656.880 0.560 ;
    END
  END wbs_stb_i
  PIN wbs_we_i
    DIRECTION INPUT ;
    USE SIGNAL ;
    ANTENNAGATEAREA 1.102000 ;
    PORT
      LAYER Metal2 ;
        RECT 658.560 0.000 659.120 0.560 ;
    END
  END wbs_we_i
  OBS
      LAYER Nwell ;
        RECT 6.290 15.250 1136.670 1145.070 ;
      LAYER Metal1 ;
        RECT 6.720 15.380 1136.240 1144.940 ;
      LAYER Metal2 ;
        RECT 0.140 1160.020 0.820 1160.740 ;
        RECT 22.140 1160.020 134.100 1160.740 ;
        RECT 135.260 1160.020 138.580 1160.740 ;
        RECT 139.740 1160.020 149.780 1160.740 ;
        RECT 150.940 1160.020 171.060 1160.740 ;
        RECT 174.460 1160.020 175.540 1160.740 ;
        RECT 178.940 1160.020 181.140 1160.740 ;
        RECT 183.420 1160.020 186.740 1160.740 ;
        RECT 187.900 1160.020 188.980 1160.740 ;
        RECT 190.140 1160.020 219.220 1160.740 ;
        RECT 220.380 1160.020 222.580 1160.740 ;
        RECT 225.980 1160.020 236.020 1160.740 ;
        RECT 237.180 1160.020 238.260 1160.740 ;
        RECT 239.420 1160.020 247.220 1160.740 ;
        RECT 248.380 1160.020 249.460 1160.740 ;
        RECT 250.620 1160.020 283.060 1160.740 ;
        RECT 286.460 1160.020 297.620 1160.740 ;
        RECT 298.780 1160.020 308.820 1160.740 ;
        RECT 309.980 1160.020 371.540 1160.740 ;
        RECT 372.700 1160.020 383.860 1160.740 ;
        RECT 385.020 1160.020 518.260 1160.740 ;
        RECT 520.540 1160.020 573.140 1160.740 ;
        RECT 574.300 1160.020 657.140 1160.740 ;
        RECT 658.300 1160.020 704.180 1160.740 ;
        RECT 705.340 1160.020 788.180 1160.740 ;
        RECT 789.340 1160.020 836.340 1160.740 ;
        RECT 837.500 1160.020 840.820 1160.740 ;
        RECT 841.980 1160.020 843.060 1160.740 ;
        RECT 844.220 1160.020 865.460 1160.740 ;
        RECT 866.620 1160.020 884.500 1160.740 ;
        RECT 885.660 1160.020 911.380 1160.740 ;
        RECT 912.540 1160.020 928.180 1160.740 ;
        RECT 929.340 1160.020 946.100 1160.740 ;
        RECT 947.260 1160.020 1006.580 1160.740 ;
        RECT 1007.740 1160.020 1008.820 1160.740 ;
        RECT 1009.980 1160.020 1136.100 1160.740 ;
        RECT 0.140 0.860 1136.100 1160.020 ;
        RECT 0.140 0.140 0.820 0.860 ;
        RECT 233.820 0.140 247.220 0.860 ;
        RECT 248.380 0.140 262.900 0.860 ;
        RECT 266.300 0.140 279.700 0.860 ;
        RECT 280.860 0.140 281.940 0.860 ;
        RECT 283.100 0.140 313.300 0.860 ;
        RECT 314.460 0.140 324.500 0.860 ;
        RECT 325.660 0.140 336.820 0.860 ;
        RECT 337.980 0.140 344.660 0.860 ;
        RECT 345.820 0.140 363.700 0.860 ;
        RECT 364.860 0.140 365.940 0.860 ;
        RECT 367.100 0.140 378.260 0.860 ;
        RECT 379.420 0.140 448.820 0.860 ;
        RECT 454.460 0.140 463.380 0.860 ;
        RECT 464.540 0.140 465.620 0.860 ;
        RECT 466.780 0.140 471.220 0.860 ;
        RECT 472.380 0.140 481.300 0.860 ;
        RECT 483.580 0.140 484.660 0.860 ;
        RECT 485.820 0.140 500.340 0.860 ;
        RECT 501.500 0.140 512.660 0.860 ;
        RECT 513.820 0.140 516.020 0.860 ;
        RECT 517.180 0.140 531.700 0.860 ;
        RECT 532.860 0.140 537.300 0.860 ;
        RECT 538.460 0.140 541.780 0.860 ;
        RECT 542.940 0.140 549.620 0.860 ;
        RECT 553.020 0.140 557.460 0.860 ;
        RECT 558.620 0.140 564.180 0.860 ;
        RECT 565.340 0.140 591.060 0.860 ;
        RECT 592.220 0.140 597.780 0.860 ;
        RECT 598.940 0.140 639.220 0.860 ;
        RECT 640.380 0.140 654.900 0.860 ;
        RECT 660.540 0.140 672.820 0.860 ;
        RECT 675.100 0.140 681.780 0.860 ;
        RECT 685.180 0.140 687.380 0.860 ;
        RECT 689.660 0.140 729.940 0.860 ;
        RECT 731.100 0.140 840.820 0.860 ;
        RECT 843.100 0.140 915.860 0.860 ;
        RECT 917.020 0.140 964.020 0.860 ;
        RECT 965.180 0.140 1067.060 0.860 ;
        RECT 1068.220 0.140 1120.820 0.860 ;
        RECT 1121.980 0.140 1136.100 0.860 ;
      LAYER Metal3 ;
        RECT 0.090 1130.940 1142.400 1152.340 ;
        RECT 0.090 1129.780 1142.100 1130.940 ;
        RECT 0.090 1080.540 1142.400 1129.780 ;
        RECT 0.860 1078.260 1142.400 1080.540 ;
        RECT 0.090 1068.220 1142.400 1078.260 ;
        RECT 0.860 1067.060 1142.400 1068.220 ;
        RECT 0.090 996.540 1142.400 1067.060 ;
        RECT 0.860 995.380 1142.400 996.540 ;
        RECT 0.090 981.980 1142.400 995.380 ;
        RECT 0.860 980.820 1142.400 981.980 ;
        RECT 0.090 979.740 1142.400 980.820 ;
        RECT 0.860 978.580 1142.400 979.740 ;
        RECT 0.090 961.820 1142.400 978.580 ;
        RECT 0.860 960.660 1142.400 961.820 ;
        RECT 0.090 958.460 1142.400 960.660 ;
        RECT 0.860 957.300 1142.400 958.460 ;
        RECT 0.090 936.060 1142.400 957.300 ;
        RECT 0.860 934.900 1142.400 936.060 ;
        RECT 0.090 794.940 1142.400 934.900 ;
        RECT 0.860 793.780 1142.400 794.940 ;
        RECT 0.090 783.740 1142.400 793.780 ;
        RECT 0.090 782.580 1142.100 783.740 ;
        RECT 0.090 781.500 1142.400 782.580 ;
        RECT 0.090 780.340 1142.100 781.500 ;
        RECT 0.090 777.020 1142.400 780.340 ;
        RECT 0.090 775.860 1142.100 777.020 ;
        RECT 0.090 745.660 1142.400 775.860 ;
        RECT 0.090 744.500 1142.100 745.660 ;
        RECT 0.090 726.620 1142.400 744.500 ;
        RECT 0.090 725.460 1142.100 726.620 ;
        RECT 0.090 712.060 1142.400 725.460 ;
        RECT 0.860 707.580 1142.400 712.060 ;
        RECT 0.860 707.540 1142.100 707.580 ;
        RECT 0.090 705.340 1142.100 707.540 ;
        RECT 0.860 705.300 1142.100 705.340 ;
        RECT 0.860 704.180 1142.400 705.300 ;
        RECT 0.090 695.260 1142.400 704.180 ;
        RECT 0.090 694.100 1142.100 695.260 ;
        RECT 0.090 679.580 1142.400 694.100 ;
        RECT 0.090 677.340 1142.100 679.580 ;
        RECT 0.860 676.180 1142.100 677.340 ;
        RECT 0.090 673.980 1142.100 676.180 ;
        RECT 0.860 672.820 1142.100 673.980 ;
        RECT 0.090 634.780 1142.400 672.820 ;
        RECT 0.090 633.620 1142.100 634.780 ;
        RECT 0.090 632.540 1142.400 633.620 ;
        RECT 0.860 631.380 1142.400 632.540 ;
        RECT 0.090 630.300 1142.400 631.380 ;
        RECT 0.860 629.140 1142.400 630.300 ;
        RECT 0.090 602.300 1142.400 629.140 ;
        RECT 0.860 601.140 1142.400 602.300 ;
        RECT 0.090 579.900 1142.400 601.140 ;
        RECT 0.860 578.780 1142.400 579.900 ;
        RECT 0.860 578.740 1142.100 578.780 ;
        RECT 0.090 577.620 1142.100 578.740 ;
        RECT 0.090 569.820 1142.400 577.620 ;
        RECT 0.860 568.660 1142.400 569.820 ;
        RECT 0.090 564.220 1142.400 568.660 ;
        RECT 0.090 563.060 1142.100 564.220 ;
        RECT 0.090 532.860 1142.400 563.060 ;
        RECT 0.860 531.700 1142.400 532.860 ;
        RECT 0.090 483.580 1142.400 531.700 ;
        RECT 0.090 482.420 1142.100 483.580 ;
        RECT 0.090 465.660 1142.400 482.420 ;
        RECT 0.090 464.500 1142.100 465.660 ;
        RECT 0.090 449.980 1142.400 464.500 ;
        RECT 0.090 448.820 1142.100 449.980 ;
        RECT 0.090 217.020 1142.400 448.820 ;
        RECT 0.860 215.860 1142.400 217.020 ;
        RECT 0.090 96.060 1142.400 215.860 ;
        RECT 0.860 91.540 1142.400 96.060 ;
        RECT 0.090 77.020 1142.400 91.540 ;
        RECT 0.090 75.860 1142.100 77.020 ;
        RECT 0.090 74.780 1142.400 75.860 ;
        RECT 0.090 73.620 1142.100 74.780 ;
        RECT 0.090 40.060 1142.400 73.620 ;
        RECT 0.860 3.060 1142.400 40.060 ;
        RECT 0.090 0.700 1142.400 3.060 ;
      LAYER Metal4 ;
        RECT 11.340 1145.240 1119.860 1152.390 ;
        RECT 11.340 17.450 21.940 1145.240 ;
        RECT 24.140 17.450 25.240 1145.240 ;
        RECT 27.440 17.450 175.540 1145.240 ;
        RECT 177.740 17.450 178.840 1145.240 ;
        RECT 181.040 17.450 329.140 1145.240 ;
        RECT 331.340 17.450 332.440 1145.240 ;
        RECT 334.640 17.450 482.740 1145.240 ;
        RECT 484.940 17.450 486.040 1145.240 ;
        RECT 488.240 17.450 636.340 1145.240 ;
        RECT 638.540 17.450 639.640 1145.240 ;
        RECT 641.840 17.450 789.940 1145.240 ;
        RECT 792.140 17.450 793.240 1145.240 ;
        RECT 795.440 17.450 943.540 1145.240 ;
        RECT 945.740 17.450 946.840 1145.240 ;
        RECT 949.040 17.450 1097.140 1145.240 ;
        RECT 1099.340 17.450 1100.440 1145.240 ;
        RECT 1102.640 17.450 1119.860 1145.240 ;
  END
END aes_core
END LIBRARY

